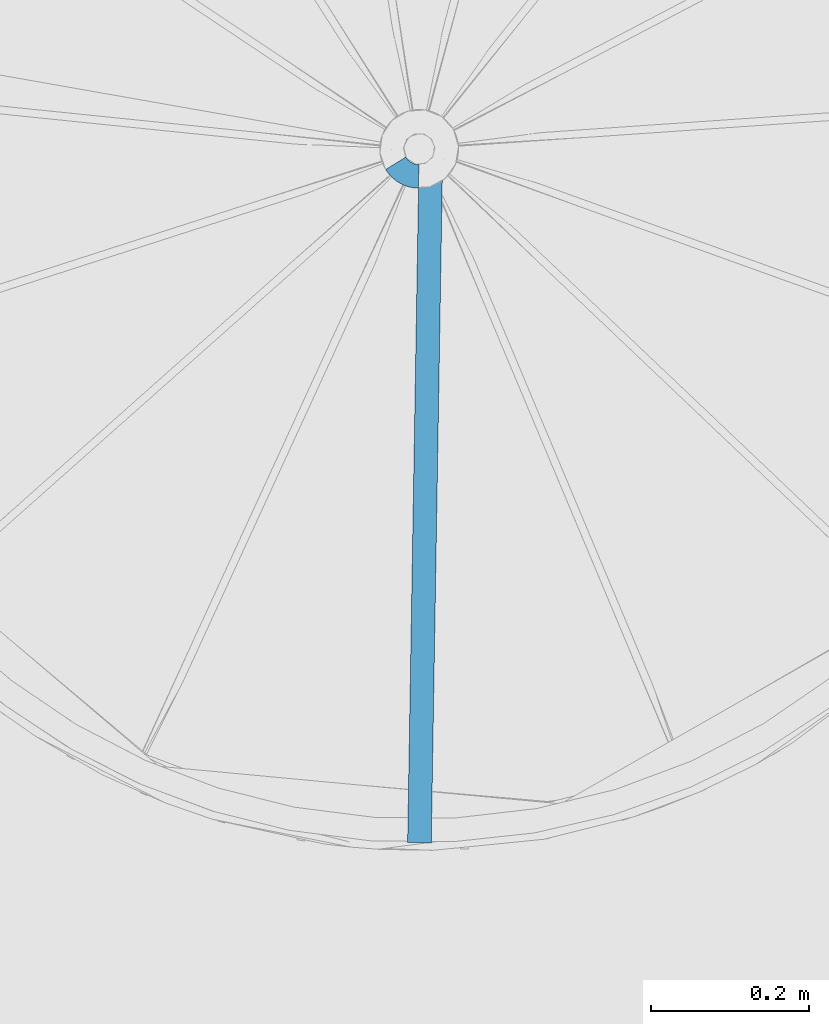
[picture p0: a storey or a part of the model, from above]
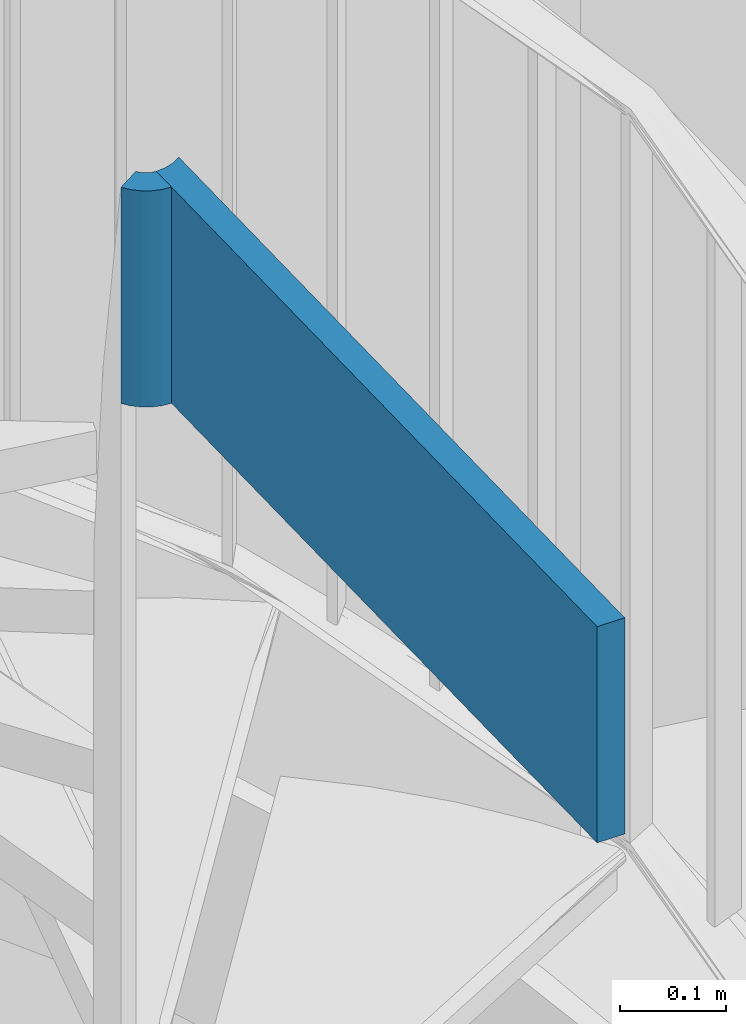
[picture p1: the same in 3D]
Properties of the parts of a building model (IFC2X3), part 1 of 2

# File
Description: ViewDefinition [CoordinationView_V2.0]
File name: 18021c
Time: 2021-05-19T17:37:48
Written by: The EXPRESS Data Manager Version 5.02.0100.07 : 28 Aug 2013
Made in: 20200826_1250(x64) - Exporter 20.2.1.0 - Alternate UI 20.2.1.0
Comment: STEP Physical File produced by: The EXPRESS Data Manager Version 5.02.0100.07 : 28 Aug 2013 * Module: EDMstepFileFactory/EDMstandAlone * Creation date: Wed May 19 17:37:48 2021 * Host: WS-1905 * Database: C:\Users\HDC~1.RDH\AppData\Local\Temp\51318361-dd76-45ec-ba82-957046c431c0\c4a6451b-f70e-414c-8df4-ee8861f415a2\ifc * Database version: 5507 * Database creation date: Wed May 19 17:37:37 2021 * Schema: IFC2X3 * Model: DataRepository.ifc * Model creation date: Wed May 19 17:37:37 2021 * Header model: DataRepository.ifc_HeaderModel * Header model creation date: Wed May 19 17:37:37 2021 * EDMuser: sdai-user * EDMgroup: sdai-group * License ID and type: 5605 : Permanent license. Expiry date: * EDMstepFileFactory options: 020000

# IfcProject, 18021c
LongName: JRCZ Fase 3 Ecologie; Phase: DO

# IfcSite, <Kadaster Gemeente>;<Kadaster nummer>;<Kadaster sectie>
RefLatitude: 51, 29, 42, 435607; RefLongitude: 3, 36, 32, 61710; RefElevation: 0 mm
Pset_ProductRequirements - Category: Project Information

# IfcBuilding, JRCZ Middelburg
LongName: JRCZ Middelburg
Pset_BuildingCommon - NumberOfStoreys: 5
Pset_ProductRequirements - Category: Project Information

# IfcBuildingStorey: Level:00_level_rechts_1.8mm verkort (5)
In: JRCZ Middelburg
Pset_ProductRequirements - Category: Levels
Name | LongName = Pset_AirSideSystemInformation, Name = Pset_ProductRequirements, Name | Elevation (mm)
-1 kelder | -1 kelder | -4000
00 begane grond | 00 begane grond | 0
01 eerste verdieping | 01 eerste verdieping | 3000
02 tweede verdieping | 02 tweede verdieping | 3700
03 dak | 03 dak | 6000

# IfcBeam: M_Dimension Lumber:180x550 (4)
Type - Pset_BeamCommon - IsExternal: no; LoadBearing: yes; Reference: 180x550
Type - Pset_ProductRequirements - Category: Structural Framing
Type - Pset_QuantityTakeOff - Reference: 180x550
Type - Pset_ReinforcementBarPitchOfBeam - Reference: 180x550
Material: Softwood, Lumber
Pset_BeamCommon - Slope: 0 deg
Pset_QuantityTakeOff - sets with these values: 2
Name (M_Dimension Lumber:180x550:...) | In | Span (mm)
1747457 | 01 eerste verdieping | 5968.59
1747506 | 01 eerste verdieping | 5680
1748045 | 02 tweede verdieping | 6266.1
1748047 | 02 tweede verdieping | 6533.1

# IfcBeam: M_Dimension Lumber:71 x 271 (31)
In: 01 eerste verdieping
Type - Pset_BeamCommon - IsExternal: no; LoadBearing: yes; Reference: 71 x 271
Type - Pset_ProductRequirements - Category: Structural Framing
Type - Pset_QuantityTakeOff - Reference: 71 x 271
Type - Pset_ReinforcementBarPitchOfBeam - Reference: 71 x 271
Material: Softwood, Lumber
Pset_BeamCommon - Slope: 0 deg; Span: 7200 mm
Pset_QuantityTakeOff - sets with these values: 2
Name (M_Dimension Lumber:71 x 271:...)
2881486
2881488
2881490
2881492
2881494
2881496
2881498
2881500
2881502
2881504
2881506
2881508
2881510
2881512
2881514
2881516
2881518
2881520
2881522
2881524
2881526
2881528
2881530
2881532
2881534
2881536
2881538
2881540
2881542
2881544
2881546

# IfcBuildingElementProxy: Hogeschool gebouw1:Hogeschool gebouw, Hogeschool gebouw1:Hogeschool gebouw:2096273
In: 00 begane grond
Type - Material: Default wit
Type - Pset_BuildingElementProxyCommon - Reference: Hogeschool gebouw
Type - Pset_ProductRequirements - Category: Mass
Type - Pset_QuantityTakeOff - Reference: Hogeschool gebouw
Material: Default wit (6)
Pset_BuildingElementProxyCommon - sets with these values: 2

# IfcBuildingElementProxy: Kolommen:Kolommen, Kolommen:Kolommen:2648048
In: 00 begane grond
Type - Material: Staal
Type - Pset_BuildingElementProxyCommon - Reference: Kolommen
Type - Pset_ProductRequirements - Category: Generic Models
Type - Pset_QuantityTakeOff - Reference: Kolommen
Material: Staal (17), Beton
Pset_BuildingElementProxyCommon - sets with these values: 2
Pset_ProvisionForVoid - Width: 4960 mm; Depth: 4960 mm

# IfcBuildingElementProxy: lbk 3:lbk 1, lbk 3:lbk 1:1831866
In: 03 dak
Type - Material: Default wit
Type - Pset_BuildingElementProxyCommon - Reference: lbk 1
Type - Pset_ProductRequirements - Category: Mass
Type - Pset_QuantityTakeOff - Reference: lbk 1
Pset_BuildingElementProxyCommon - sets with these values: 2
Pset_ProvisionForVoid - Width: 1100 mm; Height: 1300 mm; Depth: 1100 mm

# IfcBuildingElementProxy: lbk 4:lbk 1, lbk 4:lbk 1:1831894
In: 03 dak
Type - Material: Default wit
Type - Pset_BuildingElementProxyCommon - Reference: lbk 1
Type - Pset_ProductRequirements - Category: Mass
Type - Pset_QuantityTakeOff - Reference: lbk 1
Pset_BuildingElementProxyCommon - sets with these values: 2
Pset_ProvisionForVoid - Width: 1100 mm; Height: 1300 mm; Depth: 1100 mm

# IfcBuildingElementProxy: waterbak2:waterbak, waterbak2:waterbak:2452146
In: 02 tweede verdieping
Type - Material: Default wit
Type - Pset_BuildingElementProxyCommon - Reference: waterbak
Type - Pset_ProductRequirements - Category: Mass
Type - Pset_QuantityTakeOff - Reference: waterbak
Pset_BuildingElementProxyCommon - sets with these values: 2
Pset_ProvisionForVoid - Width: 900 mm; Depth: 900 mm

# IfcBuildingElementProxy: waterbak3:waterbak, waterbak3:waterbak:2452175
In: 02 tweede verdieping
Type - Material: Default wit
Type - Pset_BuildingElementProxyCommon - Reference: waterbak
Type - Pset_ProductRequirements - Category: Mass
Type - Pset_QuantityTakeOff - Reference: waterbak
Pset_BuildingElementProxyCommon - sets with these values: 2
Pset_ProvisionForVoid - Width: 900 mm; Depth: 900 mm

# IfcColumn: M_Timber-Column:180x180 (3)
In: 00 begane grond
Type - PredefinedType: COLUMN; Material: Softwood, Lumber
Type - Pset_ColumnCommon - IsExternal: no; Reference: 180x180; LoadBearing: yes
Type - Pset_ProductRequirements - Category: Structural Columns
Type - Pset_QuantityTakeOff - Reference: 180x180
Type - Pset_ReinforcementBarPitchOfColumn - Reference: 180x180
Pset_QuantityTakeOff - sets with these values: 2
Name (M_Timber-Column:180x180:...) | Slope (deg)
1657394 | 0
1657616 | 0
1657631

# IfcCurtainWall: Curtain Wall:NLRS_28_CW_hsb rek 63x196mm h.o.h. 1200mm 2 (7)
Type - Pset_CurtainWallCommon - IsExternal: no; Reference: NLRS_28_CW_hsb rek 63x196mm h.o.h. 1200mm 2
Type - Pset_ManufacturerTypeInformation - Manufacturer: ITANNEX
Type - Pset_ProductRequirements - Category: Walls
Type - Pset_QuantityTakeOff - Reference: NLRS_28_CW_hsb rek 63x196mm h.o.h. 1200mm 2
Pset_CurtainWallCommon - IsExternal: yes
Name (Curtain Wall:NLRS_28_CW_hsb rek 63x196mm h.o.h. 1200mm 2:...) | In
2779010 | 01 eerste verdieping
2779018 | 01 eerste verdieping
2779360 | 01 eerste verdieping
2779361 | 01 eerste verdieping
2780039 | 02 tweede verdieping
2780053 | 02 tweede verdieping
2780060 | 02 tweede verdieping

# IfcCurtainWall: Curtain Wall:NLRS_28_CW_hsb rek 63x196mm h.o.h. 800mm, Curtain Wall:NLRS_28_CW_hsb rek 63x196mm h.o.h. 800mm:2779345
In: 01 eerste verdieping
Type - Pset_CurtainWallCommon - IsExternal: no; Reference: NLRS_28_CW_hsb rek 63x196mm h.o.h. 800mm
Type - Pset_ManufacturerTypeInformation - Manufacturer: ITANNEX
Type - Pset_ProductRequirements - Category: Walls
Type - Pset_QuantityTakeOff - Reference: NLRS_28_CW_hsb rek 63x196mm h.o.h. 800mm
Pset_CurtainWallCommon - IsExternal: yes

# IfcCurtainWall: Curtain Wall:NLRS_31_CW_Ontwerpkozijn 067x114 (6)
Type - Pset_CurtainWallCommon - IsExternal: no; Reference: NLRS_31_CW_Ontwerpkozijn 067x114
Type - Pset_ManufacturerTypeInformation - Manufacturer: ITANNEX
Type - Pset_ProductRequirements - Category: Walls
Type - Pset_QuantityTakeOff - Reference: NLRS_31_CW_Ontwerpkozijn 067x114
Name (Curtain Wall:NLRS_31_CW_Ontwerpkozijn 067x114:...) | In | Group
1771511 | 00 begane grond | Model Group:H05:2174889 | Pset_CurtainWallCommon - IsExternal: yes
1830644 | 00 begane grond | Model Group:H04:1830654 | Pset_CurtainWallCommon - IsExternal: yes
2359723 | 02 tweede verdieping | Model Group:H01:2359729 | Pset_OpeningElementCommon - Reference: NLRS_31_CW_Ontwerpkozijn 067x114; sets with these values: 2
2384861 | 00 begane grond | Model Group:H02:1830591 | Pset_OpeningElementCommon - Reference: NLRS_31_CW_Ontwerpkozijn 067x114; sets with these values: 2
2384906 | 00 begane grond | Model Group:H03:2384882 | Pset_OpeningElementCommon - Reference: NLRS_31_CW_Ontwerpkozijn 067x114; sets with these values: 2
2775503 | 00 begane grond | Model Group:H02:1978079 | Pset_CurtainWallCommon - IsExternal: yes

# IfcCurtainWall: Curtain Wall:NLRS_31_CW_Ontwerpkozijn 067x114 2 (23)
Type - Pset_CurtainWallCommon - IsExternal: no; Reference: NLRS_31_CW_Ontwerpkozijn 067x114 2
Type - Pset_ManufacturerTypeInformation - Manufacturer: ITANNEX
Type - Pset_ProductRequirements - Category: Walls
Type - Pset_QuantityTakeOff - Reference: NLRS_31_CW_Ontwerpkozijn 067x114 2
Name (Curtain Wall:NLRS_31_CW_Ontwerpkozijn 067x114 2:...) | In | IsExternal | Group
2287266 | 01 eerste verdieping | yes | Model Group:H07:2287249
2760790 | 00 begane grond | yes | Model Group:H08:2161338
2760800 | 00 begane grond | yes | Model Group:H08:2161338
2760810 | 00 begane grond | yes | Model Group:H08:2161338
2760820 | 00 begane grond | yes | Model Group:H08:2161338
2760830 | 00 begane grond | yes | Model Group:H08:2161338
2760840 | 00 begane grond | yes | Model Group:H08:2161338
2760850 | 00 begane grond | yes | Model Group:H08:2161338
2760860 | 00 begane grond | yes | Model Group:H08:2161338
2760870 | 00 begane grond | yes | Model Group:H08:2161338
2760880 | 00 begane grond | yes | Model Group:H08:2161338
2760890 | 00 begane grond | yes | Model Group:H08:2161338
2761305 | 02 tweede verdieping |  | Model Group:H09:1979223 | Pset_OpeningElementCommon - Reference: NLRS_31_CW_Ontwerpkozijn 067x114 2; sets with these values: 2
2761315 | 02 tweede verdieping |  | Model Group:H09:1979223 | Pset_OpeningElementCommon - Reference: NLRS_31_CW_Ontwerpkozijn 067x114 2; sets with these values: 2
2763741 | 02 tweede verdieping | yes | Model Group:H10:2055879
2763751 | 02 tweede verdieping | yes | Model Group:H10:2055879
2763761 | 02 tweede verdieping | yes | Model Group:H10:2055879
2763771 | 02 tweede verdieping | yes | Model Group:H10:2055879
2763781 | 02 tweede verdieping | yes | Model Group:H10:2055879
2763791 | 02 tweede verdieping | yes | Model Group:H10:2055879
2764322 | 02 tweede verdieping |  | Model Group:H11:2764105 | Pset_OpeningElementCommon - Reference: NLRS_31_CW_Ontwerpkozijn 067x114 2; sets with these values: 2
2764332 | 02 tweede verdieping |  | Model Group:H11:2764105 | Pset_OpeningElementCommon - Reference: NLRS_31_CW_Ontwerpkozijn 067x114 2; sets with these values: 2
2764342 | 02 tweede verdieping |  | Model Group:H11:2764105 | Pset_OpeningElementCommon - Reference: NLRS_31_CW_Ontwerpkozijn 067x114 2; sets with these values: 2

# IfcCurtainWall: Curtain Wall:NLRS_31_CW_hsb rek 63x196mm h.o.h. 800mm (23)
Type - Pset_CurtainWallCommon - IsExternal: no; Reference: NLRS_31_CW_hsb rek 63x196mm h.o.h. 800mm
Type - Pset_ManufacturerTypeInformation - Manufacturer: ITANNEX
Type - Pset_ProductRequirements - Category: Walls
Type - Pset_QuantityTakeOff - Reference: NLRS_31_CW_hsb rek 63x196mm h.o.h. 800mm
Name (Curtain Wall:NLRS_31_CW_hsb rek 63x196mm h.o.h. 800mm:...) | In | IsExternal | Group
2287262 | 01 eerste verdieping | yes | Model Group:H07:2287249
2760786 | 00 begane grond | yes | Model Group:H08:2161338
2760796 | 00 begane grond | yes | Model Group:H08:2161338
2760806 | 00 begane grond | yes | Model Group:H08:2161338
2760816 | 00 begane grond | yes | Model Group:H08:2161338
2760826 | 00 begane grond | yes | Model Group:H08:2161338
2760836 | 00 begane grond | yes | Model Group:H08:2161338
2760846 | 00 begane grond | yes | Model Group:H08:2161338
2760856 | 00 begane grond | yes | Model Group:H08:2161338
2760866 | 00 begane grond | yes | Model Group:H08:2161338
2760876 | 00 begane grond | yes | Model Group:H08:2161338
2760886 | 00 begane grond | yes | Model Group:H08:2161338
2761301 | 02 tweede verdieping |  | Model Group:H09:1979223 | Pset_OpeningElementCommon - Reference: NLRS_31_CW_hsb rek 63x196mm h.o.h. 800mm; sets with these values: 2
2761311 | 02 tweede verdieping |  | Model Group:H09:1979223 | Pset_OpeningElementCommon - Reference: NLRS_31_CW_hsb rek 63x196mm h.o.h. 800mm; sets with these values: 2
2763737 | 02 tweede verdieping | yes | Model Group:H10:2055879
2763747 | 02 tweede verdieping | yes | Model Group:H10:2055879
2763757 | 02 tweede verdieping | yes | Model Group:H10:2055879
2763767 | 02 tweede verdieping | yes | Model Group:H10:2055879
2763777 | 02 tweede verdieping | yes | Model Group:H10:2055879
2763787 | 02 tweede verdieping | yes | Model Group:H10:2055879
2764318 | 02 tweede verdieping |  | Model Group:H11:2764105 | Pset_OpeningElementCommon - Reference: NLRS_31_CW_hsb rek 63x196mm h.o.h. 800mm; sets with these values: 2
2764328 | 02 tweede verdieping |  | Model Group:H11:2764105 | Pset_OpeningElementCommon - Reference: NLRS_31_CW_hsb rek 63x196mm h.o.h. 800mm; sets with these values: 2
2764338 | 02 tweede verdieping |  | Model Group:H11:2764105 | Pset_OpeningElementCommon - Reference: NLRS_31_CW_hsb rek 63x196mm h.o.h. 800mm; sets with these values: 2

# IfcCurtainWall: Curtain Wall:NLRS_32_CW_Ontwerpkozijn 067x114, Curtain Wall:NLRS_32_CW_Ontwerpkozijn 067x114:2362233
In: 00 begane grond
Type - Pset_CurtainWallCommon - IsExternal: no; Reference: NLRS_32_CW_Ontwerpkozijn 067x114
Type - Pset_ManufacturerTypeInformation - Manufacturer: ITANNEX
Type - Pset_ProductRequirements - Category: Walls
Type - Pset_QuantityTakeOff - Reference: NLRS_32_CW_Ontwerpkozijn 067x114
Pset_OpeningElementCommon - Reference: NLRS_32_CW_Ontwerpkozijn 067x114; sets with these values: 2
Group: Model Group:H06:2017390

# IfcCurtainWall: Curtain Wall:NLRS_32_CW_Ontwerpkozijn 067x114 binnen (4)
Type - Pset_CurtainWallCommon - IsExternal: no; Reference: NLRS_32_CW_Ontwerpkozijn 067x114 binnen
Type - Pset_ManufacturerTypeInformation - Manufacturer: ITANNEX
Type - Pset_ProductRequirements - Category: Walls
Type - Pset_QuantityTakeOff - Reference: NLRS_32_CW_Ontwerpkozijn 067x114 binnen
Name (Curtain Wall:NLRS_32_CW_Ontwerpkozijn 067x114 binnen:...) | In | Reference | sets with these values
1745974 | 00 begane grond | NLRS_32_CW_Ontwerpkozijn 067x114 binnen | 2
1766168 | 00 begane grond | NLRS_32_CW_Ontwerpkozijn 067x114 binnen | 2
1772871 | 02 tweede verdieping | NLRS_32_CW_Ontwerpkozijn 067x114 binnen | 2 | Group: Model Group:32_dubbele deur:2147310
1820701 | 00 begane grond | Group: Model Group:32_kozijn_meterkast:1986720; Pset_CurtainWallCommon - IsExternal: yes

# IfcCurtainWall: Curtain Wall:Vliesgevel C, Curtain Wall:Vliesgevel C:2317173
In: 00 begane grond
Type - Pset_CurtainWallCommon - IsExternal: no; Reference: Vliesgevel C
Type - Pset_ManufacturerTypeInformation - Manufacturer: ITANNEX
Type - Pset_ProductRequirements - Category: Walls
Type - Pset_QuantityTakeOff - Reference: Vliesgevel C
Pset_CurtainWallCommon - IsExternal: yes
Group: Model Group:vliesgevel C:2317233

# IfcCurtainWall: Curtain Wall:vliesgevel A, Curtain Wall:vliesgevel A:1692366
In: 00 begane grond
Type - Pset_CurtainWallCommon - IsExternal: no; Reference: vliesgevel A
Type - Pset_ManufacturerTypeInformation - Manufacturer: ITANNEX
Type - Pset_ProductRequirements - Category: Walls
Type - Pset_QuantityTakeOff - Reference: vliesgevel A
Pset_CurtainWallCommon - IsExternal: yes
Group: Model Group:vliesgevel A:2175042

# IfcCurtainWall: Curtain Wall:vliesgevel B, Curtain Wall:vliesgevel B:1745524
In: 00 begane grond
Type - Pset_CurtainWallCommon - IsExternal: no; Reference: vliesgevel B
Type - Pset_ManufacturerTypeInformation - Manufacturer: ITANNEX
Type - Pset_ProductRequirements - Category: Walls
Type - Pset_QuantityTakeOff - Reference: vliesgevel B
Pset_CurtainWallCommon - IsExternal: yes
Group: Model Group:Vliesgevel B:2773624

# IfcDistributionPort (6)
Description: Flow
Name | FlowDirection
2 x Port_1755777 | SOURCE
Port_1755777 | SINK
2 x Port_1786391 | SOURCE
Port_1786391 | SINK

# IfcDoor: 31_DO_deur_0:binnendeur (2)
In: 00 begane grond
Type - ParameterTakesPrecedence: no; Sizeable: no; Material: <Unnamed> (2)
Type - Pset_DoorCommon - IsExternal: no; Reference: binnendeur
Type - Pset_ManufacturerTypeInformation - Manufacturer: ITANNEX
Type - Pset_ProductRequirements - Category: Doors
Type - Pset_QuantityTakeOff - Reference: binnendeur
OverallHeight: 1933 mm; Group: Model Group:32_kozijn_meterkast:1986720
Pset_DoorCommon - IsExternal: yes
Name (31_DO_deur_0:binnendeur:...) | OverallWidth (mm)
1820702 | 557.55
1820844 | 588.45

# IfcDoor: 31_DO_deur_0:binnendeur 2 (2)
In: 00 begane grond
Type - ParameterTakesPrecedence: no; Sizeable: no; Material: <Unnamed> (2)
Type - Pset_DoorCommon - IsExternal: no; Reference: binnendeur 2
Type - Pset_ManufacturerTypeInformation - Manufacturer: ITANNEX
Type - Pset_ProductRequirements - Category: Doors
Type - Pset_QuantityTakeOff - Reference: binnendeur 2
OverallHeight: 2333 mm; Group: Model Group:H06:2017390
Pset_DoorCommon - IsExternal: yes
Name (31_DO_deur_0:binnendeur 2:...) | OverallWidth (mm)
2362234 | 557.55
2362239 | 588.45

# IfcDoor: 31_DO_deur_0:deur (6)
Type - ParameterTakesPrecedence: no; Sizeable: no; Material: RBM_a_deur_paneel (2)
Type - Pset_DoorCommon - IsExternal: no; Reference: deur
Type - Pset_ManufacturerTypeInformation - Manufacturer: ITANNEX
Type - Pset_ProductRequirements - Category: Doors
Type - Pset_QuantityTakeOff - Reference: deur
OverallHeight: 2333 mm
Pset_DoorCommon - IsExternal: yes
Name (31_DO_deur_0:deur:...) | In | OverallWidth (mm) | Group
1830645 | 00 begane grond | 833 | Model Group:H04:1830654
1830651 | 00 begane grond | 833 | Model Group:H04:1830654
2359724 | 02 tweede verdieping | 930 | Model Group:H01:2359729
2384862 | 00 begane grond | 950 | Model Group:H02:1830591
2384907 | 00 begane grond | 950 | Model Group:H03:2384882
2775504 | 00 begane grond | 950 | Model Group:H02:1978079

# IfcDoor: 31_DO_schuifdeur_1:binnendeur, 31_DO_schuifdeur_1:binnendeur:2536623
In: 00 begane grond
Type - ParameterTakesPrecedence: no; Sizeable: no; Material: RBM_i2_binnenkozijn (2)
Type - Pset_DoorCommon - IsExternal: no; Reference: binnendeur
Type - Pset_ManufacturerTypeInformation - Manufacturer: ITANNEX
Type - Pset_ProductRequirements - Category: Doors
Type - Pset_QuantityTakeOff - Reference: binnendeur
OverallHeight: 2211.17 mm; OverallWidth: 2298.02 mm; Material: RBM_i2_binnenkozijn (4); Group: Model Group:Vliesgevel B:2773624
Pset_DoorCommon - IsExternal: yes

# IfcDoor: 31_DO_schuifdeur_1:deur, 31_DO_schuifdeur_1:deur:1693376
In: 00 begane grond
Type - ParameterTakesPrecedence: no; Sizeable: no; Material: RBM_a_kozijn licht (2)
Type - Pset_DoorCommon - IsExternal: no; Reference: deur
Type - Pset_ManufacturerTypeInformation - Manufacturer: ITANNEX
Type - Pset_ProductRequirements - Category: Doors
Type - Pset_QuantityTakeOff - Reference: deur
OverallHeight: 2366.5 mm; OverallWidth: 2124.7 mm; Material: RBM_a_kozijn licht (4); Group: Model Group:vliesgevel A:2175042
Pset_DoorCommon - IsExternal: yes

# IfcDoor: 31_DO_stolpdeur_1:0std, 31_DO_stolpdeur_1:0std:1771512
In: 00 begane grond
Type - ParameterTakesPrecedence: no; Sizeable: no; Material: RBM_a_kozijn (2)
Type - Pset_DoorCommon - IsExternal: no; Reference: 0std
Type - Pset_ManufacturerTypeInformation - Manufacturer: ITANNEX
Type - Pset_ProductRequirements - Category: Doors
Type - Pset_QuantityTakeOff - Reference: 0std
OverallHeight: 2333 mm; OverallWidth: 1533 mm; Material: RBM_a_kozijn (4); Group: Model Group:H05:2174889
Pset_DoorCommon - IsExternal: yes

# IfcDoor: 31_DO_stolpdeur_1:0std, 31_DO_stolpdeur_1:0std:2317180
In: 00 begane grond
Type - ParameterTakesPrecedence: no; Sizeable: no; Material: RBM_a_kozijn licht (2)
Type - Pset_DoorCommon - IsExternal: no; Reference: 0std
Type - Pset_ManufacturerTypeInformation - Manufacturer: ITANNEX
Type - Pset_ProductRequirements - Category: Doors
Type - Pset_QuantityTakeOff - Reference: 0std
OverallHeight: 2366.5 mm; OverallWidth: 2122.45 mm; Material: RBM_a_kozijn licht (4); Group: Model Group:vliesgevel C:2317233
Pset_DoorCommon - IsExternal: yes

# IfcDoor: 31_DO_stolpdeur_1:0std binnendeur (2)
Type - ParameterTakesPrecedence: no; Sizeable: no; Material: <Unnamed> (2)
Type - Pset_DoorCommon - IsExternal: no; Reference: 0std binnendeur
Type - Pset_ManufacturerTypeInformation - Manufacturer: ITANNEX
Type - Pset_ProductRequirements - Category: Doors
Type - Pset_QuantityTakeOff - Reference: 0std binnendeur
OverallHeight: 2333 mm; Material: <Unnamed> (4)
Pset_DoorCommon - IsExternal: yes
Name (31_DO_stolpdeur_1:0std binnendeur:...) | In | OverallWidth (mm)
1766169 | 00 begane grond | 1533
1772872 | 02 tweede verdieping | 1433 | Group: Model Group:32_dubbele deur:2147310

# IfcDoor: NLRS_32_DO_ISR_onderdeel deur-SH_generiek_ISR:dichte deur_gen, NLRS_32_DO_ISR_onderdeel deur-SH_generiek_ISR:dichte deur_gen:1765288
In: 01 eerste verdieping
Type - OperationType: SINGLE_SWING_RIGHT; ConstructionType: USERDEFINED; ParameterTakesPrecedence: no; Sizeable: no; Material: <Unnamed> (2)
Type - NLRS_32_DO_ISR_onderdeel deur-SH_generiek_ISR:dichte deur_gen:1765288 - PanelOperation: SWINGING
Type - Pset_ConcreteElementGeneral - ConstructionType: deurblad
Type - Pset_DoorCommon - IsExternal: no; Reference: dichte deur_gen
Type - Pset_ProductRequirements - Category: Doors
Type - Pset_QuantityTakeOff - Reference: dichte deur_gen
OverallHeight: 2315 mm; OverallWidth: 930 mm; Material: <Unnamed>

# IfcDoor: NLRS_32_DO_ISR_onderdeel deur-SH_generiek_ISR:dichte deur_gen, NLRS_32_DO_ISR_onderdeel deur-SH_generiek_ISR:dichte deur_gen:1774227
In: 01 eerste verdieping
Type - OperationType: SINGLE_SWING_RIGHT; ConstructionType: USERDEFINED; ParameterTakesPrecedence: no; Sizeable: no; Material: <Unnamed> (2)
Type - NLRS_32_DO_ISR_onderdeel deur-SH_generiek_ISR:dichte deur_gen:1774227 - PanelOperation: SWINGING
Type - Pset_ConcreteElementGeneral - ConstructionType: deurblad
Type - Pset_DoorCommon - IsExternal: no; Reference: dichte deur_gen
Type - Pset_ProductRequirements - Category: Doors
Type - Pset_QuantityTakeOff - Reference: dichte deur_gen
OverallHeight: 2315 mm; OverallWidth: 980 mm; Material: <Unnamed>

# IfcDoor: NLRS_32_DO_ISR_onderdeel deur-SH_generiek_ISR:dichte deur_gen (7)
Type - OperationType: SINGLE_SWING_RIGHT; ConstructionType: USERDEFINED; ParameterTakesPrecedence: no; Sizeable: no; Material: <Unnamed> (2)
Type - NLRS_32_DO_ISR_onderdeel deur-SH_generiek_ISR:dichte deur_gen:1774258 - PanelOperation: SWINGING
Type - Pset_ConcreteElementGeneral - ConstructionType: deurblad
Type - Pset_DoorCommon - IsExternal: no; Reference: dichte deur_gen
Type - Pset_ProductRequirements - Category: Doors
Type - Pset_QuantityTakeOff - Reference: dichte deur_gen
OverallHeight: 2315 mm; OverallWidth: 980 mm; Material: <Unnamed>
Name (NLRS_32_DO_ISR_onderdeel deur-SH_generiek_ISR:dichte deur_gen:...) | In
1774258 | 01 eerste verdieping
1774293 | 01 eerste verdieping
1774882 | 00 begane grond
1775023 | 00 begane grond
1823580 | 01 eerste verdieping
1823676 | 01 eerste verdieping
1830939 | 00 begane grond

# IfcDoor: NLRS_32_DO_ISR_onderdeel deur-SH_generiek_ISR:dichte deur_gen, NLRS_32_DO_ISR_onderdeel deur-SH_generiek_ISR:dichte deur_gen:1986993
In: 01 eerste verdieping
Type - OperationType: SINGLE_SWING_RIGHT; ConstructionType: USERDEFINED; ParameterTakesPrecedence: no; Sizeable: no; Material: <Unnamed> (2)
Type - NLRS_32_DO_ISR_onderdeel deur-SH_generiek_ISR:dichte deur_gen:1986993 - PanelOperation: SWINGING
Type - Pset_ConcreteElementGeneral - ConstructionType: deurblad
Type - Pset_DoorCommon - IsExternal: no; Reference: dichte deur_gen
Type - Pset_ProductRequirements - Category: Doors
Type - Pset_QuantityTakeOff - Reference: dichte deur_gen
OverallHeight: 2315 mm; OverallWidth: 880 mm; Material: <Unnamed>

# IfcDoor: NLRS_32_DO_ISR_onderdeel deur-SH_generiek_ISR:dichte deur_gen, NLRS_32_DO_ISR_onderdeel deur-SH_generiek_ISR:dichte deur_gen:2352775
In: 01 eerste verdieping
Type - OperationType: SINGLE_SWING_RIGHT; ConstructionType: USERDEFINED; ParameterTakesPrecedence: no; Sizeable: no; Material: <Unnamed> (2)
Type - NLRS_32_DO_ISR_onderdeel deur-SH_generiek_ISR:dichte deur_gen:2352775 - PanelOperation: SWINGING
Type - Pset_ConcreteElementGeneral - ConstructionType: deurblad
Type - Pset_DoorCommon - IsExternal: no; Reference: dichte deur_gen
Type - Pset_ProductRequirements - Category: Doors
Type - Pset_QuantityTakeOff - Reference: dichte deur_gen
OverallHeight: 2315 mm; OverallWidth: 880 mm; Material: <Unnamed>

# IfcDoor: NLRS_32_DO_ISR_onderdeel deur-SH_generiek_ISR:dichte deur_gen, NLRS_32_DO_ISR_onderdeel deur-SH_generiek_ISR:dichte deur_gen:2530179
In: 00 begane grond
Type - OperationType: SINGLE_SWING_RIGHT; ConstructionType: USERDEFINED; ParameterTakesPrecedence: no; Sizeable: no; Material: <Unnamed> (2)
Type - NLRS_32_DO_ISR_onderdeel deur-SH_generiek_ISR:dichte deur_gen:2530179 - PanelOperation: SWINGING
Type - Pset_ConcreteElementGeneral - ConstructionType: deurblad
Type - Pset_DoorCommon - IsExternal: no; Reference: dichte deur_gen
Type - Pset_ProductRequirements - Category: Doors
Type - Pset_QuantityTakeOff - Reference: dichte deur_gen
OverallHeight: 2315 mm; OverallWidth: 600 mm; Material: <Unnamed>

# IfcDoor: NLRS_32_DO_UN_samenstelling binnenkozijn hout-SH_generiek_ISR:enkele deur_gen (12)
Type - ConstructionType: USERDEFINED; ParameterTakesPrecedence: no; Sizeable: no; Material: <Unnamed> (2)
Type - Pset_ConcreteElementGeneral - ConstructionType: binnenkozijn hout
Type - Pset_DoorCommon - IsExternal: no; Reference: enkele deur_gen
Type - Pset_ProductRequirements - Category: Doors
Type - Pset_QuantityTakeOff - Reference: enkele deur_gen
OverallHeight: 2377 mm; Material: <Unnamed> (3)
Name (NLRS_32_DO_UN_samenstelling binnenkozijn hout-SH_generiek_ISR:enkele deur_gen:...) | In | OverallWidth (mm)
1765287 | 01 eerste verdieping | 1034
1774226 | 01 eerste verdieping | 1084
1774257 | 01 eerste verdieping | 1084
1774292 | 01 eerste verdieping | 1084
1774881 | 00 begane grond | 1084
1775022 | 00 begane grond | 1084
1823579 | 01 eerste verdieping | 1084
1823675 | 01 eerste verdieping | 1084
1830938 | 00 begane grond | 1084
1986992 | 01 eerste verdieping | 984
2352774 | 01 eerste verdieping | 984
2530178 | 00 begane grond | 704

# IfcElementAssembly: Structural Beam System:houten balkalaag 71 X 271 hoh400, Structural Beam System:houten balkalaag 71 X 271 hoh400:2881297
In: 01 eerste verdieping
PredefinedType: BEAM_GRID
Pset_ProductRequirements - Category: Structural Beam Systems
Pset_QuantityTakeOff - Reference: houten balkalaag 71 X 271 hoh400

# IfcFlowTerminal: NLRS_74_PF_FB_toilet wand_generiek_ISR:toilet_gen (2)
Type - Classification: 74.11.11 (NL/SfB); Material: <Unnamed> (2)
Type - Pset_ProductRequirements - Category: Plumbing Fixtures
Type - Pset_QuantityTakeOff - Reference: toilet_gen
Material: <Unnamed> (3)
Pset_DistributionFlowElementCommon - Reference: toilet_gen; sets with these values: 2
Name (NLRS_74_PF_FB_toilet wand_generiek_ISR:toilet_gen:...) | In
1786344 | 00 begane grond
2353124 | 01 eerste verdieping

# IfcFlowTerminal: NLRS_74_PF_FB_wastafel_generiek_ISR:wastafel_gen (2)
Type - Classification: 74.11.31 (NL/SfB); Material: <Unnamed> (2)
Type - Pset_ProductRequirements - Category: Plumbing Fixtures
Type - Pset_QuantityTakeOff - Reference: wastafel_gen
Material: <Unnamed> (8)
Pset_DistributionFlowElementCommon - Reference: wastafel_gen; sets with these values: 2
Name (NLRS_74_PF_FB_wastafel_generiek_ISR:wastafel_gen:...) | In
1755777 | 01 eerste verdieping
1786391 | 00 begane grond

# IfcFurnishingElement: NLRS_73_FUS_UN_blad_generiek_generiek_ISR:blad_gen, NLRS_73_FUS_UN_blad_generiek_generiek_ISR:blad_gen:1775840
In: 00 begane grond
Type - Classification: 73.11 vaste keukenvoorzieningen; standaard, keukenmeubilering (NL/SfB); Material: <Unnamed>
Type - Pset_ProductRequirements - Category: Furniture Systems
Type - Pset_QuantityTakeOff - Reference: blad_gen
Pset_FurnitureTypeCommon - Description: aanrechtblad

# IfcMember: Rectangular Mullion:31_CWM_067x114 (111)
Type - PredefinedType: MULLION; Classification: 31.0 (NL/SfB); Material: RBM_a_kozijn
Type - Pset_ManufacturerTypeInformation - Manufacturer: ITANNEX
Type - Pset_MemberCommon - IsExternal: no; Reference: 31_CWM_067x114
Type - Pset_ProductRequirements - Category: Curtain Wall Mullions
Type - Pset_QuantityTakeOff - Reference: 31_CWM_067x114
Pset_MemberCommon - IsExternal: yes
Name (Rectangular Mullion:31_CWM_067x114:...) | In | Span (mm) | Group
1771514 | 00 begane grond | 1533 | Model Group:H05:2174889
1771516 | 00 begane grond | 2400 | Model Group:H05:2174889
1771517 | 00 begane grond | 2400 | Model Group:H05:2174889
1830646 | 00 begane grond | 900 | Model Group:H04:1830654
1830647 | 00 begane grond | 2333 | Model Group:H04:1830654
1830648 | 00 begane grond | 2333 | Model Group:H04:1830654
1830653 | 00 begane grond | 900 | Model Group:H04:1830654
2287268 | 01 eerste verdieping | 641 | Model Group:H07:2287249
2287269 | 01 eerste verdieping | 641 | Model Group:H07:2287249
2287270 | 01 eerste verdieping | 1400 | Model Group:H07:2287249
2287271 | 01 eerste verdieping | 1400 | Model Group:H07:2287249
2359725 | 02 tweede verdieping | 930 | Model Group:H01:2359729
2359726 | 02 tweede verdieping | 2400 | Model Group:H01:2359729
2359727 | 02 tweede verdieping | 2400 | Model Group:H01:2359729
2384863 | 00 begane grond | 950 | Model Group:H02:1830591
2384864 | 00 begane grond | 2400 | Model Group:H02:1830591
2384865 | 00 begane grond | 2400 | Model Group:H02:1830591
2384908 | 00 begane grond | 950 | Model Group:H03:2384882
2384909 | 00 begane grond | 2400 | Model Group:H03:2384882
2384910 | 00 begane grond | 2400 | Model Group:H03:2384882
2760792 | 00 begane grond | 641 | Model Group:H08:2161338
2760793 | 00 begane grond | 641 | Model Group:H08:2161338
2760794 | 00 begane grond | 1200 | Model Group:H08:2161338
2760795 | 00 begane grond | 1200 | Model Group:H08:2161338
2760802 | 00 begane grond | 641 | Model Group:H08:2161338
2760803 | 00 begane grond | 641 | Model Group:H08:2161338
2760804 | 00 begane grond | 1600 | Model Group:H08:2161338
2760805 | 00 begane grond | 1600 | Model Group:H08:2161338
2760812 | 00 begane grond | 641 | Model Group:H08:2161338
2760813 | 00 begane grond | 641 | Model Group:H08:2161338
2760814 | 00 begane grond | 1400 | Model Group:H08:2161338
2760815 | 00 begane grond | 1400 | Model Group:H08:2161338
2760822 | 00 begane grond | 641 | Model Group:H08:2161338
2760823 | 00 begane grond | 641 | Model Group:H08:2161338
2760824 | 00 begane grond | 1400 | Model Group:H08:2161338
2760825 | 00 begane grond | 1400 | Model Group:H08:2161338
2760832 | 00 begane grond | 641 | Model Group:H08:2161338
2760833 | 00 begane grond | 641 | Model Group:H08:2161338
2760834 | 00 begane grond | 1200 | Model Group:H08:2161338
2760835 | 00 begane grond | 1200 | Model Group:H08:2161338
2760842 | 00 begane grond | 641 | Model Group:H08:2161338
2760843 | 00 begane grond | 641 | Model Group:H08:2161338
2760844 | 00 begane grond | 1400 | Model Group:H08:2161338
2760845 | 00 begane grond | 1400 | Model Group:H08:2161338
2760852 | 00 begane grond | 641 | Model Group:H08:2161338
2760853 | 00 begane grond | 641 | Model Group:H08:2161338
2760854 | 00 begane grond | 1600 | Model Group:H08:2161338
2760855 | 00 begane grond | 1600 | Model Group:H08:2161338
2760862 | 00 begane grond | 641 | Model Group:H08:2161338
2760863 | 00 begane grond | 641 | Model Group:H08:2161338
2760864 | 00 begane grond | 1800 | Model Group:H08:2161338
2760865 | 00 begane grond | 1800 | Model Group:H08:2161338
2760872 | 00 begane grond | 641 | Model Group:H08:2161338
2760873 | 00 begane grond | 641 | Model Group:H08:2161338
2760874 | 00 begane grond | 1600 | Model Group:H08:2161338
2760875 | 00 begane grond | 1600 | Model Group:H08:2161338
2760882 | 00 begane grond | 641 | Model Group:H08:2161338
2760883 | 00 begane grond | 641 | Model Group:H08:2161338
2760884 | 00 begane grond | 1400 | Model Group:H08:2161338
2760885 | 00 begane grond | 1400 | Model Group:H08:2161338
2760892 | 00 begane grond | 641 | Model Group:H08:2161338
2760893 | 00 begane grond | 641 | Model Group:H08:2161338
2760894 | 00 begane grond | 1600 | Model Group:H08:2161338
2760895 | 00 begane grond | 1600 | Model Group:H08:2161338
2761307 | 02 tweede verdieping | 641 | Model Group:H09:1979223
2761308 | 02 tweede verdieping | 641 | Model Group:H09:1979223
2761309 | 02 tweede verdieping | 1200 | Model Group:H09:1979223
2761310 | 02 tweede verdieping | 1200 | Model Group:H09:1979223
2761317 | 02 tweede verdieping | 641 | Model Group:H09:1979223
2761318 | 02 tweede verdieping | 641 | Model Group:H09:1979223
2761319 | 02 tweede verdieping | 1200 | Model Group:H09:1979223
2761320 | 02 tweede verdieping | 1200 | Model Group:H09:1979223
2763743 | 02 tweede verdieping | 641 | Model Group:H10:2055879
2763744 | 02 tweede verdieping | 641 | Model Group:H10:2055879
2763745 | 02 tweede verdieping | 1600 | Model Group:H10:2055879
2763746 | 02 tweede verdieping | 1600 | Model Group:H10:2055879
2763753 | 02 tweede verdieping | 641 | Model Group:H10:2055879
2763754 | 02 tweede verdieping | 641 | Model Group:H10:2055879
2763755 | 02 tweede verdieping | 1400 | Model Group:H10:2055879
2763756 | 02 tweede verdieping | 1400 | Model Group:H10:2055879
2763763 | 02 tweede verdieping | 641 | Model Group:H10:2055879
2763764 | 02 tweede verdieping | 641 | Model Group:H10:2055879
2763765 | 02 tweede verdieping | 1400 | Model Group:H10:2055879
2763766 | 02 tweede verdieping | 1400 | Model Group:H10:2055879
2763773 | 02 tweede verdieping | 641 | Model Group:H10:2055879
2763774 | 02 tweede verdieping | 641 | Model Group:H10:2055879
2763775 | 02 tweede verdieping | 1600 | Model Group:H10:2055879
2763776 | 02 tweede verdieping | 1600 | Model Group:H10:2055879
2763783 | 02 tweede verdieping | 641 | Model Group:H10:2055879
2763784 | 02 tweede verdieping | 641 | Model Group:H10:2055879
2763785 | 02 tweede verdieping | 1600 | Model Group:H10:2055879
2763786 | 02 tweede verdieping | 1600 | Model Group:H10:2055879
2763793 | 02 tweede verdieping | 641 | Model Group:H10:2055879
2763794 | 02 tweede verdieping | 641 | Model Group:H10:2055879
2763795 | 02 tweede verdieping | 1600 | Model Group:H10:2055879
2763796 | 02 tweede verdieping | 1600 | Model Group:H10:2055879
2764324 | 02 tweede verdieping | 641 | Model Group:H11:2764105
2764325 | 02 tweede verdieping | 641 | Model Group:H11:2764105
2764326 | 02 tweede verdieping | 1600 | Model Group:H11:2764105
2764327 | 02 tweede verdieping | 1600 | Model Group:H11:2764105
2764334 | 02 tweede verdieping | 641 | Model Group:H11:2764105
2764335 | 02 tweede verdieping | 641 | Model Group:H11:2764105
2764336 | 02 tweede verdieping | 1600 | Model Group:H11:2764105
2764337 | 02 tweede verdieping | 1600 | Model Group:H11:2764105
2764344 | 02 tweede verdieping | 641 | Model Group:H11:2764105
2764345 | 02 tweede verdieping | 641 | Model Group:H11:2764105
2764346 | 02 tweede verdieping | 1600 | Model Group:H11:2764105
2764347 | 02 tweede verdieping | 1600 | Model Group:H11:2764105
2775505 | 00 begane grond | 950 | Model Group:H02:1978079
2775506 | 00 begane grond | 2400 | Model Group:H02:1978079
2775507 | 00 begane grond | 2400 | Model Group:H02:1978079

# IfcMember: Rectangular Mullion:31_CWM_067x114 vliesgevel (70)
In: 00 begane grond
Type - PredefinedType: MULLION; Material: RBM_a_kozijn licht
Type - Pset_MemberCommon - IsExternal: no; Reference: 31_CWM_067x114 vliesgevel
Type - Pset_ProductRequirements - Category: Curtain Wall Mullions
Type - Pset_QuantityTakeOff - Reference: 31_CWM_067x114 vliesgevel
Pset_MemberCommon - IsExternal: yes
Name (Rectangular Mullion:31_CWM_067x114 vliesgevel:...) | Span (mm) | Group
1692369 | 1088.69 | Model Group:vliesgevel A:2175042
1692370 | 1018.56 | Model Group:vliesgevel A:2175042
1692371 | 2400 | Model Group:vliesgevel A:2175042
1692372 | 2630.8 | Model Group:vliesgevel A:2175042
1693382 | 1142.76 | Model Group:vliesgevel A:2175042
1693384 | 2299.5 | Model Group:vliesgevel A:2175042
1693456 | 1142.76 | Model Group:vliesgevel A:2175042
1693524 | 1088.61 | Model Group:vliesgevel A:2175042
1693525 | 1173.06 | Model Group:vliesgevel A:2175042
1693526 | 2299.5 | Model Group:vliesgevel A:2175042
1693767 | 1200 | Model Group:vliesgevel A:2175042
1693768 | 2400 | Model Group:vliesgevel A:2175042
1693769 | 1018.56 | Model Group:vliesgevel A:2175042
1693770 | 1139.56 | Model Group:vliesgevel A:2175042
1693771 | 1139.56 | Model Group:vliesgevel A:2175042
1693772 | 1018.64 | Model Group:vliesgevel A:2175042
1693773 | 1133 | Model Group:vliesgevel A:2175042
1693774 | 1133 | Model Group:vliesgevel A:2175042
1693775 | 1133 | Model Group:vliesgevel A:2175042
1693857 | 2964.57 | Model Group:vliesgevel A:2175042
1693858 | 1200 | Model Group:vliesgevel A:2175042
1693859 | 1018.56 | Model Group:vliesgevel A:2175042
1693860 | 1139.56 | Model Group:vliesgevel A:2175042
1693861 | 1139.56 | Model Group:vliesgevel A:2175042
1693862 | 1018.64 | Model Group:vliesgevel A:2175042
1693863 | 2678.72 | Model Group:vliesgevel A:2175042
1693864 | 2764.19 | Model Group:vliesgevel A:2175042
1693865 | 2849.65 | Model Group:vliesgevel A:2175042
2317175 | 879.488 | Model Group:vliesgevel C:2317233
2317176 | 2333 | Model Group:vliesgevel C:2317233
2317181 | 2299.5 | Model Group:vliesgevel C:2317233
2317184 | 1128.23 | Model Group:vliesgevel C:2317233
2317185 | 2299.5 | Model Group:vliesgevel C:2317233
2317188 | 1128.23 | Model Group:vliesgevel C:2317233
2317189 | 2299.5 | Model Group:vliesgevel C:2317233
2317192 | 1059.6 | Model Group:vliesgevel C:2317233
2317193 | 2299.5 | Model Group:vliesgevel C:2317233
2317201 | 1200 | Model Group:vliesgevel C:2317233
2317202 | 879.488 | Model Group:vliesgevel C:2317233
2317203 | 1094.73 | Model Group:vliesgevel C:2317233
2317204 | 1094.73 | Model Group:vliesgevel C:2317233
2317205 | 1094.73 | Model Group:vliesgevel C:2317233
2317206 | 1094.73 | Model Group:vliesgevel C:2317233
2317207 | 992.604 | Model Group:vliesgevel C:2317233
2317208 | 1133 | Model Group:vliesgevel C:2317233
2317209 | 1133 | Model Group:vliesgevel C:2317233
2317210 | 1133 | Model Group:vliesgevel C:2317233
2317211 | 1133 | Model Group:vliesgevel C:2317233
2317212 | 1133 | Model Group:vliesgevel C:2317233
2317220 | 2635.22 | Model Group:vliesgevel C:2317233
2317221 | 879.488 | Model Group:vliesgevel C:2317233
2317222 | 1094.73 | Model Group:vliesgevel C:2317233
2317223 | 1094.73 | Model Group:vliesgevel C:2317233
2317224 | 1094.73 | Model Group:vliesgevel C:2317233
2317225 | 992.604 | Model Group:vliesgevel C:2317233
2317226 | 2841.7 | Model Group:vliesgevel C:2317233
2317227 | 2760.84 | Model Group:vliesgevel C:2317233
2317228 | 2679.99 | Model Group:vliesgevel C:2317233
2317235 | 3106.82 | Model Group:vliesgevel C:2317233
2317236 | 2400 | Model Group:vliesgevel C:2317233
2317237 | 1200 | Model Group:vliesgevel C:2317233
2317238 | 3003.41 | Model Group:vliesgevel C:2317233
2317239 | 1062.49 | Model Group:vliesgevel C:2317233
2317240 | 1097.71 | Model Group:vliesgevel C:2317233
2317241 | 1097.71 | Model Group:vliesgevel C:2317233
2317242 | 949.066 | Model Group:vliesgevel C:2317233
2317243 | 1097.71 | Model Group:vliesgevel C:2317233
2317244 | 1097.71 | Model Group:vliesgevel C:2317233
2317245 | 1094.73 | Model Group:vliesgevel C:2317233
2317246 | 2922.56 | Model Group:vliesgevel C:2317233

# IfcMember: Rectangular Mullion:32_CWM_067x114 (108)
Type - PredefinedType: MULLION; Material: RBM_i2_binnenkozijn
Type - Pset_MemberCommon - IsExternal: no; Reference: 32_CWM_067x114
Type - Pset_ProductRequirements - Category: Curtain Wall Mullions
Type - Pset_QuantityTakeOff - Reference: 32_CWM_067x114
Pset_MemberCommon - IsExternal: yes
Name (Rectangular Mullion:32_CWM_067x114:...) | In | Span (mm) | Group
1745529 | 00 begane grond | 2211.17 | Model Group:Vliesgevel B:2773624
1745530 | 00 begane grond | 2177.67 | Model Group:Vliesgevel B:2773624
1748685 | 00 begane grond | 2144.17 | Model Group:Vliesgevel B:2773624
2530423 | 00 begane grond | 1165.92 | Model Group:Vliesgevel B:2773624
2532656 | 00 begane grond | 1290.67 | Model Group:Vliesgevel B:2773624
2532657 | 00 begane grond | 1832.67 | Model Group:Vliesgevel B:2773624
2532658 | 00 begane grond | 2177.67 | Model Group:Vliesgevel B:2773624
2532659 | 00 begane grond | 820 | Model Group:Vliesgevel B:2773624
2532660 | 00 begane grond | 1290.67 | Model Group:Vliesgevel B:2773624
2532661 | 00 begane grond | 2007.36 | Model Group:Vliesgevel B:2773624
2532662 | 00 begane grond | 1098.92 | Model Group:Vliesgevel B:2773624
2532663 | 00 begane grond | 1202.39 | Model Group:Vliesgevel B:2773624
2533105 | 00 begane grond | 1199.3 | Model Group:Vliesgevel B:2773624
2533106 | 00 begane grond | 1175.38 | Model Group:Vliesgevel B:2773624
2533510 | 00 begane grond | 786.5 | Model Group:Vliesgevel B:2773624
2533511 | 00 begane grond | 1357.67 | Model Group:Vliesgevel B:2773624
2533512 | 00 begane grond | 1098.92 | Model Group:Vliesgevel B:2773624
2533513 | 00 begane grond | 1202.39 | Model Group:Vliesgevel B:2773624
2533514 | 00 begane grond | 786.5 | Model Group:Vliesgevel B:2773624
2534488 | 00 begane grond | 1169.01 | Model Group:Vliesgevel B:2773624
2534489 | 00 begane grond | 1205.77 | Model Group:Vliesgevel B:2773624
2534490 | 00 begane grond | 1172.27 | Model Group:Vliesgevel B:2773624
2534491 | 00 begane grond | 1172.27 | Model Group:Vliesgevel B:2773624
2534493 | 00 begane grond | 2144.17 | Model Group:Vliesgevel B:2773624
2534494 | 00 begane grond | 1290.67 | Model Group:Vliesgevel B:2773624
2534495 | 00 begane grond | 786.5 | Model Group:Vliesgevel B:2773624
2534496 | 00 begane grond | 2092.75 | Model Group:Vliesgevel B:2773624
2535008 | 00 begane grond | 1205.56 | Model Group:Vliesgevel B:2773624
2535010 | 00 begane grond | 1196.14 | Model Group:Vliesgevel B:2773624
2535011 | 00 begane grond | 1196.14 | Model Group:Vliesgevel B:2773624
2535014 | 00 begane grond | 1290.67 | Model Group:Vliesgevel B:2773624
2535015 | 00 begane grond | 786.5 | Model Group:Vliesgevel B:2773624
2535016 | 00 begane grond | 1919.79 | Model Group:Vliesgevel B:2773624
1745993 | 00 begane grond | 833.5
1745994 | 00 begane grond | 800
1746000 | 00 begane grond | 833.5
1746001 | 00 begane grond | 800
1746002 | 00 begane grond | 833.5
1746007 | 00 begane grond | 2400
1746008 | 00 begane grond | 2266
1746009 | 00 begane grond | 2266
1746010 | 00 begane grond | 2266
1766038 | 00 begane grond | 833.5
1766039 | 00 begane grond | 2266
1766175 | 00 begane grond | 1633.5
1766178 | 00 begane grond | 867
1766179 | 00 begane grond | 2400
1766180 | 00 begane grond | 2333
1766182 | 00 begane grond | 2266
1766185 | 00 begane grond | 833.5
1766186 | 00 begane grond | 2266
1772881 | 02 tweede verdieping | 2400 | Model Group:32_dubbele deur:2147310
1772882 | 02 tweede verdieping | 2400 | Model Group:32_dubbele deur:2147310
1773055 | 02 tweede verdieping | 1433 | Model Group:32_dubbele deur:2147310
1820737 | 00 begane grond | 655.45 | Model Group:32_kozijn_meterkast:1986720
1820739 | 00 begane grond | 1933 | Model Group:32_kozijn_meterkast:1986720
1820740 | 00 begane grond | 1933 | Model Group:32_kozijn_meterkast:1986720
1820850 | 00 begane grond | 624.55 | Model Group:32_kozijn_meterkast:1986720
2287264 | 01 eerste verdieping | 1400 | Model Group:H07:2287249
2287265 | 01 eerste verdieping | 1400 | Model Group:H07:2287249
2362235 | 00 begane grond | 655.45 | Model Group:H06:2017390
2362236 | 00 begane grond | 2333 | Model Group:H06:2017390
2362237 | 00 begane grond | 2333 | Model Group:H06:2017390
2362240 | 00 begane grond | 624.55 | Model Group:H06:2017390
2760788 | 00 begane grond | 1200 | Model Group:H08:2161338
2760789 | 00 begane grond | 1200 | Model Group:H08:2161338
2760798 | 00 begane grond | 1600 | Model Group:H08:2161338
2760799 | 00 begane grond | 1600 | Model Group:H08:2161338
2760808 | 00 begane grond | 1400 | Model Group:H08:2161338
2760809 | 00 begane grond | 1400 | Model Group:H08:2161338
2760818 | 00 begane grond | 1400 | Model Group:H08:2161338
2760819 | 00 begane grond | 1400 | Model Group:H08:2161338
2760828 | 00 begane grond | 1200 | Model Group:H08:2161338
2760829 | 00 begane grond | 1200 | Model Group:H08:2161338
2760838 | 00 begane grond | 1400 | Model Group:H08:2161338
2760839 | 00 begane grond | 1400 | Model Group:H08:2161338
2760848 | 00 begane grond | 1600 | Model Group:H08:2161338
2760849 | 00 begane grond | 1600 | Model Group:H08:2161338
2760858 | 00 begane grond | 1800 | Model Group:H08:2161338
2760859 | 00 begane grond | 1800 | Model Group:H08:2161338
2760868 | 00 begane grond | 1600 | Model Group:H08:2161338
2760869 | 00 begane grond | 1600 | Model Group:H08:2161338
2760878 | 00 begane grond | 1400 | Model Group:H08:2161338
2760879 | 00 begane grond | 1400 | Model Group:H08:2161338
2760888 | 00 begane grond | 1600 | Model Group:H08:2161338
2760889 | 00 begane grond | 1600 | Model Group:H08:2161338
2761303 | 02 tweede verdieping | 1200 | Model Group:H09:1979223
2761304 | 02 tweede verdieping | 1200 | Model Group:H09:1979223
2761313 | 02 tweede verdieping | 1200 | Model Group:H09:1979223
2761314 | 02 tweede verdieping | 1200 | Model Group:H09:1979223
2763739 | 02 tweede verdieping | 1600 | Model Group:H10:2055879
2763740 | 02 tweede verdieping | 1600 | Model Group:H10:2055879
2763749 | 02 tweede verdieping | 1400 | Model Group:H10:2055879
2763750 | 02 tweede verdieping | 1400 | Model Group:H10:2055879
2763759 | 02 tweede verdieping | 1400 | Model Group:H10:2055879
2763760 | 02 tweede verdieping | 1400 | Model Group:H10:2055879
2763769 | 02 tweede verdieping | 1600 | Model Group:H10:2055879
2763770 | 02 tweede verdieping | 1600 | Model Group:H10:2055879
2763779 | 02 tweede verdieping | 1600 | Model Group:H10:2055879
2763780 | 02 tweede verdieping | 1600 | Model Group:H10:2055879
2763789 | 02 tweede verdieping | 1600 | Model Group:H10:2055879
2763790 | 02 tweede verdieping | 1600 | Model Group:H10:2055879
2764320 | 02 tweede verdieping | 1600 | Model Group:H11:2764105
2764321 | 02 tweede verdieping | 1600 | Model Group:H11:2764105
2764330 | 02 tweede verdieping | 1600 | Model Group:H11:2764105
2764331 | 02 tweede verdieping | 1600 | Model Group:H11:2764105
2764340 | 02 tweede verdieping | 1600 | Model Group:H11:2764105
2764341 | 02 tweede verdieping | 1600 | Model Group:H11:2764105

# IfcMember: Rectangular Mullion:dakbalk_80x160 (28)
In: 03 dak
Type - PredefinedType: MULLION; Material: Staal
Type - Pset_MemberCommon - IsExternal: no; Reference: dakbalk_80x160
Type - Pset_ProductRequirements - Category: Curtain Wall Mullions
Type - Pset_QuantityTakeOff - Reference: dakbalk_80x160
Pset_MemberCommon - IsExternal: yes
Name (Rectangular Mullion:dakbalk_80x160:...) | Span (mm)
2777961 | 3454.18
2777962 | 3282.54
2777963 | 3002.74
2777964 | 2722.94
2777965 | 2443.14
2778003 | 1992.09
2778011 | 3116.65
2778025 | 2163.35
2778029 | 2739.28
2778039 | 3679.08
2779122 | 2554.4
2779166 | 1883.6
2781827 | 1182.44
2777926 | 3113.53
2777927 | 4517.87
2777928 | 4795.45
2777929 | 4961.57
2777930 | 5675.57
2777931 | 6103.02
2777932 | 6530.4
2777933 | 6448.29
2777934 | 2256.63
2777935 | 2705.15
2777936 | 3153.58
2777972 | 3573.82
2778046 | 5128
2778193 | 6957.74
2780549 | 3078.76

# IfcMember: Rectangular Mullion:kolom rond 90 (20)
Type - PredefinedType: MULLION; Material: Staal
Type - Pset_MemberCommon - IsExternal: no; Reference: kolom rond 90
Type - Pset_ProductRequirements - Category: Curtain Wall Mullions
Type - Pset_QuantityTakeOff - Reference: kolom rond 90
Pset_MemberCommon - IsExternal: yes
Name (Rectangular Mullion:kolom rond 90:...) | In | Span (mm)
2779022 | 01 eerste verdieping | 3590.76
2779031 | 01 eerste verdieping | 4084.09
2779034 | 01 eerste verdieping | 3957.34
2779037 | 01 eerste verdieping | 3830.87
2779040 | 01 eerste verdieping | 3702.84
2779043 | 01 eerste verdieping | 4165.72
2779357 | 01 eerste verdieping | 2363.76
2779358 | 01 eerste verdieping | 2485.95
2779378 | 01 eerste verdieping | 2394.5
2779369 | 01 eerste verdieping | 2644
2779371 | 01 eerste verdieping | 2892.42
2779372 | 01 eerste verdieping | 2768.24
2780049 | 02 tweede verdieping | 2118.59
2780050 | 02 tweede verdieping | 1997.85
2780051 | 02 tweede verdieping | 1877.19
2780052 | 02 tweede verdieping | 1756.72
2780071 | 02 tweede verdieping | 1632.84
2780055 | 02 tweede verdieping | 2494.51
2780066 | 02 tweede verdieping | 2320.82
2780067 | 02 tweede verdieping | 2200.04

# IfcMember: Stringer:RBM_trapboom hout_300x50 (4)
Type - PredefinedType: STRINGER
Material: traphout
Pset_MemberCommon - IsExternal: no; Reference: RBM_trapboom hout_300x50
Pset_ProductRequirements - Category: Supports
Pset_QuantityTakeOff - Reference: RBM_trapboom hout_300x50
Name (Assembled Stair:Stair:...) | In | Slope (deg)
1659339 Stringer 1 | 01 eerste verdieping | 36.6743
1659339 Stringer 2 | 01 eerste verdieping | 36.6743
1742392 Stringer 1 | 00 begane grond | 90
1742392 Stringer 2 | 00 begane grond | 42.2737

# IfcMember: Stringer:Stringer - vluchttrap (11)
Type - PredefinedType: STRINGER
Material: <Unnamed>
Pset_MemberCommon - IsExternal: no; Reference: Stringer - vluchttrap
Pset_ProductRequirements - Category: Supports
Pset_QuantityTakeOff - Reference: Stringer - vluchttrap
Name (Assembled Stair:Stair:...) | In | Slope (deg)
2174468 Stringer 1 | -1 kelder | 84.09 | Group: Model Group:trap naar kelder:2174486
2174468 Stringer 2 | -1 kelder | 28.7617 | Group: Model Group:trap naar kelder:2174486
2174468 Stringer 3 | -1 kelder | 0 | Group: Model Group:trap naar kelder:2174486
2174468 Stringer 4 | -1 kelder | 0 | Group: Model Group:trap naar kelder:2174486
2451970 Stringer 1 | 00 begane grond | 90
2451970 Stringer 2 | 00 begane grond | 25.407
2451970 Stringer 3 | 00 begane grond | 0
2451970 Stringer 4 | 00 begane grond | 0
2451970 Stringer 5 | 00 begane grond | 0
2451970 Stringer 6 | 00 begane grond | 0
2451970 Stringer 7 | 00 begane grond | 0

# IfcOpeningElement: Opening (50)
Name | In | Reference | sets with these values | Category
Basic Wall:22_hsb_binnenwand_gips_318,5mm:1641471:1 | 00 begane grond | 22_hsb_binnenwand_gips_318,5mm | 2 | Walls | Pset_ElementShading - Roughness: 304.8 mm
2 x Basic Wall:22_hsb_binnenwand_gips_318,5mm:1641471 | 00 begane grond | NLRS_32_CW_Ontwerpkozijn 067x114 binnen | 2 | Walls | Pset_ManufacturerTypeInformation - Manufacturer: ITANNEX
Basic Wall:22_WA_metalstud_binnenwand_100mm:2391560 | 01 eerste verdieping
2 x Basic Wall:22_hsb_binnenwand_gips_318,5mm:1641685 | 00 begane grond | 22_hsb_binnenwand_gips_318,5mm | 2 | Rectangular Straight Wall Opening | Pset_ElementShading - Roughness: 304.8 mm
Basic Wall:21_RBM_WA_hsb_270mm - geïsoleerd:1643321 | 00 begane grond | NLRS_32_CW_Ontwerpkozijn 067x114 | 2 | Walls | Pset_ManufacturerTypeInformation - Manufacturer: ITANNEX
Basic Wall:22_hsb_binnenwand_gips_318,5mm:1653860 | 02 tweede verdieping | NLRS_32_CW_Ontwerpkozijn 067x114 binnen | 2 | Walls | Pset_ManufacturerTypeInformation - Manufacturer: ITANNEX
Basic Wall:22_hsb_binnenwand_gips_318,5mm:1653861 | 01 eerste verdieping | enkel_gen_bxh 930x2315 | 2 | Doors
Basic Wall:22_hsb_binnenwand_gips_318,5mm:1653861 | 01 eerste verdieping | enkel_gen_bxh 880x2315 | 2 | Doors
 | 02 tweede verdieping | RBM_23_FL_houten kanaalplaat-320mm | 2 | Floors | Pset_ElementShading - Roughness: 304.8 mm
2 x Basic Wall:22_WA_metalstud_binnenwand_100mm:1657880 | 01 eerste verdieping | enkel_gen_bxh 980x2315 | 2 | Doors
 | 01 eerste verdieping | RBM_23_FL_underlayment 19 mm | 2 | Floors | Pset_ElementShading - Roughness: 304.8 mm
Basic Wall:22_hsb_binnenwand_gips_318,5mm:1660133 | 01 eerste verdieping | enkel_gen_bxh 930x2315 | 2 | Doors
Basic Wall:22_hsb_binnenwand_gips_318,5mm:1660133 | 01 eerste verdieping | enkel_gen_bxh 880x2315 | 2 | Doors
Basic Wall:22_WA_metalstud_binnenwand_100mm:1749211 | 01 eerste verdieping
Basic Wall:22_WA_metalstud_binnenwand_100mm:1658055 | 01 eerste verdieping
Basic Wall:22_WA_metalstud_binnenwand_100mm:1657975 | 01 eerste verdieping
4 x Basic Wall:22_WA_metalstud_binnenwand_100mm:1657880 | 01 eerste verdieping
Basic Wall:22_WA_metalstud_binnenwand_100mm:1657769 | 00 begane grond
Basic Wall:22_WA_metalstud_binnenwand_100mm:1657728 | 00 begane grond
2 x Basic Wall:22_hsb_binnenwand_gips_318,5mm:1641685 | 00 begane grond
Basic Wall:21_RBM_WA_hsb_270mm - geïsoleerd:1778975 | 00 begane grond | NLRS_31_CW_Ontwerpkozijn 067x114 | 2 | Walls | Pset_ManufacturerTypeInformation - Manufacturer: ITANNEX
3 x Basic Wall:21_RBM_WA_hsb_270mm_ rockpanel:1886505 | 02 tweede verdieping | NLRS_31_CW_Ontwerpkozijn 067x114 2 | 2 | Walls | Pset_ManufacturerTypeInformation - Manufacturer: ITANNEX
3 x Basic Wall:21_RBM_WA_hsb_270mm_ rockpanel:1886505 | 02 tweede verdieping | NLRS_31_CW_hsb rek 63x196mm h.o.h. 800mm | 2 | Walls | Pset_ManufacturerTypeInformation - Manufacturer: ITANNEX
Basic Wall:21_RBM_WA_hsb_270mm_houten bekleding:1886670 | 00 begane grond | NLRS_31_CW_Ontwerpkozijn 067x114 | 2 | Walls | Pset_ManufacturerTypeInformation - Manufacturer: ITANNEX
2 x Basic Wall:21_RBM_WA_hsb_270mm_houten bekleding:1887040 | 01 eerste verdieping | NLRS_31_CW_hsb rek 63x196mm h.o.h. 800mm | 2 | Walls | Pset_ManufacturerTypeInformation - Manufacturer: ITANNEX
2 x Basic Wall:21_RBM_WA_hsb_270mm_houten bekleding:1887040 | 01 eerste verdieping | NLRS_31_CW_Ontwerpkozijn 067x114 2 | 2 | Walls | Pset_ManufacturerTypeInformation - Manufacturer: ITANNEX
Basic Wall:21_RBM_WA_hsb_270mm_ rockpanel:1887983 | 00 begane grond | NLRS_31_CW_Ontwerpkozijn 067x114 | 2 | Walls | Pset_ManufacturerTypeInformation - Manufacturer: ITANNEX
Basic Wall:21_RBM_WA_hsb_270mm_ rockpanel:1888420 | 00 begane grond | NLRS_31_CW_Ontwerpkozijn 067x114 | 2 | Walls | Pset_ManufacturerTypeInformation - Manufacturer: ITANNEX
Basic Wall:21_RBM_WA_hsb_270mm_ rockpanel:1888480 | 02 tweede verdieping | NLRS_31_CW_Ontwerpkozijn 067x114 | 2 | Walls | Pset_ManufacturerTypeInformation - Manufacturer: ITANNEX
Basic Wall:22_hsb_binnenwand_gips_318,5mm:1970625 | 00 begane grond | NLRS_32_CW_Ontwerpkozijn 067x114 binnen | 2 | Walls | Pset_ManufacturerTypeInformation - Manufacturer: ITANNEX
Basic Wall:21_RBM_WA_hsb_270mm_ rockpanel:2454753 | 02 tweede verdieping | NLRS_31_CW_Ontwerpkozijn 067x114 | 2 | Walls | Pset_ManufacturerTypeInformation - Manufacturer: ITANNEX
 | 01 eerste verdieping | RBM_23_FL_Fermacell_zwevende_dekvloer | 2 | Floors | Pset_ElementShading - Roughness: 304.8 mm
Floor:RBM_23_FL_Fermacell_zwevende_dekvloer:2631502:2 | 01 eerste verdieping | RBM_23_FL_Fermacell_zwevende_dekvloer | 2 | Floors | Pset_ElementShading - Roughness: 304.8 mm
Basic Wall:21_RBM_WA_dakrand/pas strook_rockpanel:2515202 | 02 tweede verdieping | 21_RBM_WA_dakrand/pas strook_rockpanel | 2 | <Sketch> | Pset_ElementShading - Roughness: 304.8 mm
Basic Wall:21_RBM_WA_dakrand/pas strook_rockpanel:2682410 | 03 dak | Vliesgevel C | 2 | Walls | Pset_ManufacturerTypeInformation - Manufacturer: ITANNEX
Basic Wall:21_RBM_WA_hsb_270mm_houten bekleding:2747179 | 00 begane grond | vliesgevel A | 2 | Walls | Pset_ManufacturerTypeInformation - Manufacturer: ITANNEX
Basic Wall:22_hsb_270 passtrook + gips:2752812 | 02 tweede verdieping | NLRS_32_CW_Ontwerpkozijn 067x114 binnen | 2 | Walls | Pset_ManufacturerTypeInformation - Manufacturer: ITANNEX

# IfcPlate: System Panel:31_CWP_glas_1 (26)
In: 00 begane grond
Type - PredefinedType: CURTAIN_PANEL; Classification: 31.11 buitenwandopeningen; niet gevuld, daglichtopeningen (NL/SfB); Material: o1_glas
Type - Pset_ManufacturerTypeInformation - Manufacturer: ITANNEX
Type - Pset_PlateCommon - IsExternal: no; Reference: 31_CWP_glas_1
Type - Pset_ProductRequirements - Category: Curtain Panels
Type - Pset_QuantityTakeOff - Reference: 31_CWP_glas_1
Pset_PlateCommon - IsExternal: yes
Name (System Panel:31_CWP_glas_1:...) | Group
1692367 | Model Group:vliesgevel A:2175042
1693517 | Model Group:vliesgevel A:2175042
1693751 | Model Group:vliesgevel A:2175042
1693752 | Model Group:vliesgevel A:2175042
1693753 | Model Group:vliesgevel A:2175042
1693754 | Model Group:vliesgevel A:2175042
1693841 | Model Group:vliesgevel A:2175042
1693842 | Model Group:vliesgevel A:2175042
1693843 | Model Group:vliesgevel A:2175042
1693844 | Model Group:vliesgevel A:2175042
2317174 | Model Group:vliesgevel C:2317233
2317183 | Model Group:vliesgevel C:2317233
2317187 | Model Group:vliesgevel C:2317233
2317191 | Model Group:vliesgevel C:2317233
2317195 | Model Group:vliesgevel C:2317233
2317196 | Model Group:vliesgevel C:2317233
2317197 | Model Group:vliesgevel C:2317233
2317198 | Model Group:vliesgevel C:2317233
2317199 | Model Group:vliesgevel C:2317233
2317200 | Model Group:vliesgevel C:2317233
2317214 | Model Group:vliesgevel C:2317233
2317215 | Model Group:vliesgevel C:2317233
2317216 | Model Group:vliesgevel C:2317233
2317217 | Model Group:vliesgevel C:2317233
2317218 | Model Group:vliesgevel C:2317233
2317219 | Model Group:vliesgevel C:2317233

# IfcPlate: System Panel:31_CWP_glas_2 (23)
Type - PredefinedType: CURTAIN_PANEL; Material: o1_glas
Type - Pset_PlateCommon - IsExternal: no; Reference: 31_CWP_glas_2
Type - Pset_ProductRequirements - Category: Curtain Panels
Type - Pset_QuantityTakeOff - Reference: 31_CWP_glas_2
Pset_PlateCommon - IsExternal: yes
Name (System Panel:31_CWP_glas_2:...) | In | Group
2287267 | 01 eerste verdieping | Model Group:H07:2287249
2760791 | 00 begane grond | Model Group:H08:2161338
2760801 | 00 begane grond | Model Group:H08:2161338
2760811 | 00 begane grond | Model Group:H08:2161338
2760821 | 00 begane grond | Model Group:H08:2161338
2760831 | 00 begane grond | Model Group:H08:2161338
2760841 | 00 begane grond | Model Group:H08:2161338
2760851 | 00 begane grond | Model Group:H08:2161338
2760861 | 00 begane grond | Model Group:H08:2161338
2760871 | 00 begane grond | Model Group:H08:2161338
2760881 | 00 begane grond | Model Group:H08:2161338
2760891 | 00 begane grond | Model Group:H08:2161338
2761306 | 02 tweede verdieping | Model Group:H09:1979223
2761316 | 02 tweede verdieping | Model Group:H09:1979223
2763742 | 02 tweede verdieping | Model Group:H10:2055879
2763752 | 02 tweede verdieping | Model Group:H10:2055879
2763762 | 02 tweede verdieping | Model Group:H10:2055879
2763772 | 02 tweede verdieping | Model Group:H10:2055879
2763782 | 02 tweede verdieping | Model Group:H10:2055879
2763792 | 02 tweede verdieping | Model Group:H10:2055879
2764323 | 02 tweede verdieping | Model Group:H11:2764105
2764333 | 02 tweede verdieping | Model Group:H11:2764105
2764343 | 02 tweede verdieping | Model Group:H11:2764105

# IfcPlate: System Panel:32_CWP_glas (14)
In: 00 begane grond
Type - PredefinedType: CURTAIN_PANEL; Material: o1_glas
Type - Pset_PlateCommon - IsExternal: no; Reference: 32_CWP_glas
Type - Pset_ProductRequirements - Category: Curtain Panels
Type - Pset_QuantityTakeOff - Reference: 32_CWP_glas
Pset_PlateCommon - IsExternal: yes
Name (System Panel:32_CWP_glas:...) | Group
1745525 | Model Group:Vliesgevel B:2773624
2534468 | Model Group:Vliesgevel B:2773624
2532248 | Model Group:Vliesgevel B:2773624
2534469 | Model Group:Vliesgevel B:2773624
2532249 | Model Group:Vliesgevel B:2773624
2534730 | Model Group:Vliesgevel B:2773624
2533499 | Model Group:Vliesgevel B:2773624
2534470 | Model Group:Vliesgevel B:2773624
2533500 | Model Group:Vliesgevel B:2773624
2534731 | Model Group:Vliesgevel B:2773624
1745975
1745978
1745980
1766173

# IfcRailing: Railing:NLRS_90_RA_LB_hekwerk panelen_gen (3)
Pset_ProductRequirements - Category: Railings
Pset_QuantityTakeOff - Reference: NLRS_90_RA_LB_hekwerk panelen_gen
Pset_RailingCommon - IsExternal: no; Reference: NLRS_90_RA_LB_hekwerk panelen_gen; Height: 1219.2 mm
Name (Railing:NLRS_90_RA_LB_hekwerk panelen_gen:...) | In | Material
2451973 | 00 begane grond | <Unnamed> (20), h2_staal_gen (6)
2452008 | 00 begane grond | <Unnamed> (86), h2_staal_gen (8)
2452040 | 02 tweede verdieping | <Unnamed> (17), h2_staal_gen (2)
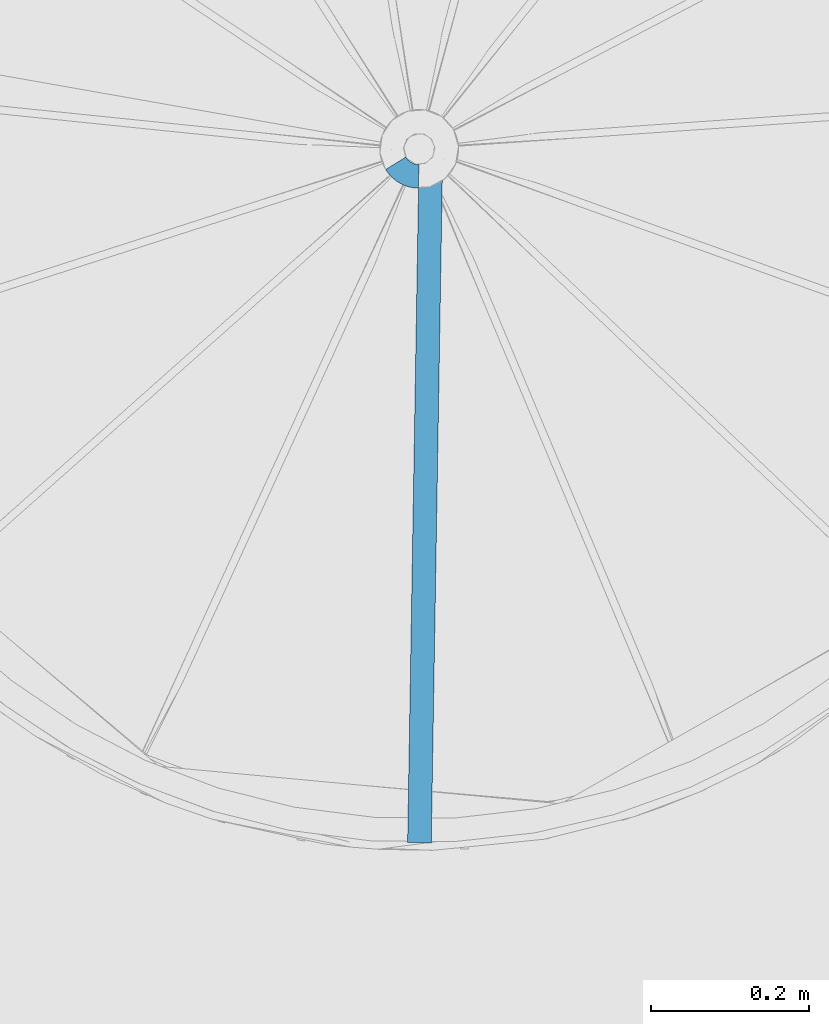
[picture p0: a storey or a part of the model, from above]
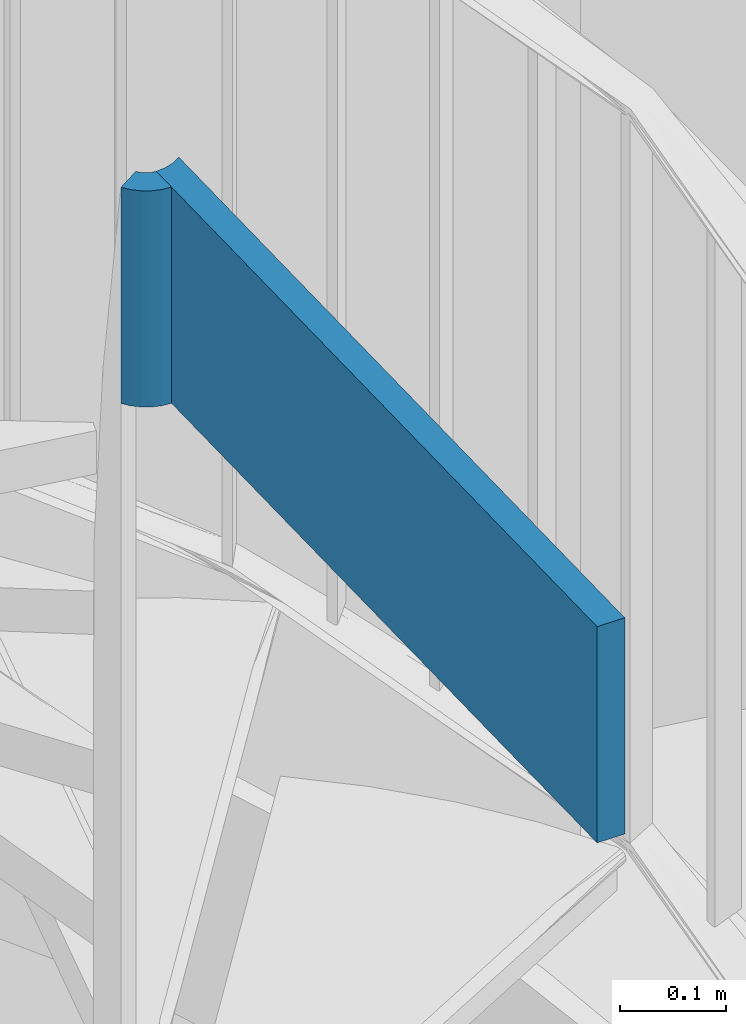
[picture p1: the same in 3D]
Properties of the parts of a building model (IFC2X3), part 2 of 2

# IfcRailing: Railing:NLRS_90_RA_LB_hekwerk panelen_laag (2)
Pset_ProductRequirements - Category: Railings
Pset_QuantityTakeOff - Reference: NLRS_90_RA_LB_hekwerk panelen_laag
Pset_RailingCommon - IsExternal: no; Reference: NLRS_90_RA_LB_hekwerk panelen_laag; Height: 1219.2 mm
Group: Model Group:trap naar kelder:2174486
Name (Railing:NLRS_90_RA_LB_hekwerk panelen_laag:...) | In | Material
2174470 | -1 kelder | <Unnamed> (68), h2_staal_gen (4)
2174483 | 00 begane grond | <Unnamed> (51), h2_staal_gen (2)

# IfcRailing: Railing:NLRS_90_RA_LB_hekwerk spijlen staal, Railing:NLRS_90_RA_LB_hekwerk spijlen staal:2887061
In: 02 tweede verdieping
Material: <Unnamed> (97), h2_staal_gen
Pset_ProductRequirements - Category: Railings
Pset_QuantityTakeOff - Reference: NLRS_90_RA_LB_hekwerk spijlen staal
Pset_RailingCommon - IsExternal: no; Reference: NLRS_90_RA_LB_hekwerk spijlen staal; Height: 1219.2 mm

# IfcRailing: Railing:NLRS_90_RA_LB_hekwerk spijlen staal +trapboom (2)
In: 02 tweede verdieping
Material: <Unnamed> (15), h2_staal_gen (2)
Pset_ProductRequirements - Category: Railings
Pset_QuantityTakeOff - Reference: NLRS_90_RA_LB_hekwerk spijlen staal +trapboom
Pset_RailingCommon - IsExternal: no; Reference: NLRS_90_RA_LB_hekwerk spijlen staal +trapboom; Height: 1219.2 mm
Name (Railing:NLRS_90_RA_LB_hekwerk spijlen staal +trapboom:...)
2871537
2871541

# IfcRailing: Railing:RBM_RA_glasbalustrade (8)
Pset_ProductRequirements - Category: Railings
Pset_QuantityTakeOff - Reference: RBM_RA_glasbalustrade
Pset_RailingCommon - IsExternal: no; Reference: RBM_RA_glasbalustrade; Height: 1066.8 mm
Name (Railing:RBM_RA_glasbalustrade:...) | In | Material
2876911 | 02 tweede verdieping | Glass_RIPO (2), <Unnamed>
2877435 | 00 begane grond | Glass_RIPO, <Unnamed>
2878266 | 02 tweede verdieping | Glass_RIPO, <Unnamed>
2878645 | 02 tweede verdieping | Glass_RIPO, <Unnamed>
2879326 | 02 tweede verdieping | Glass_RIPO, <Unnamed>
2879408 | 02 tweede verdieping | Glass_RIPO, <Unnamed>
2879637 | 02 tweede verdieping | Glass_RIPO, <Unnamed>
2879737 | 02 tweede verdieping | Glass_RIPO, <Unnamed>

# IfcRailing: Railing:RBM_RA_glasbalustrade 02 TRAP (2)
Material: Glass_RIPO, <Unnamed>
Pset_ProductRequirements - Category: Railings
Pset_QuantityTakeOff - Reference: RBM_RA_glasbalustrade 02 TRAP
Pset_RailingCommon - IsExternal: no; Reference: RBM_RA_glasbalustrade 02 TRAP; Height: 1066.8 mm
Name (Railing:RBM_RA_glasbalustrade 02 TRAP:...) | In
2877431 | 00 begane grond
2878579 | 01 eerste verdieping

# IfcRailing: Railing:RBM_RA_handleuning (3)
Material: <Unnamed>
Pset_ProductRequirements - Category: Railings
Pset_QuantityTakeOff - Reference: RBM_RA_handleuning
Pset_RailingCommon - IsExternal: no; Reference: RBM_RA_handleuning; Height: 1066.8 mm
Name (Railing:RBM_RA_handleuning:...) | In
2879164 | 02 tweede verdieping
2879217 | 02 tweede verdieping
2879233 | 01 eerste verdieping

# IfcRoof: Basic Roof:Dak_isolatie goot, Basic Roof:Dak_isolatie goot:2599447
In: 03 dak
Pset_ElementShading - Roughness: 304.8 mm
Pset_ProductRequirements - Category: Roofs
Pset_QuantityTakeOff - Reference: Dak_isolatie goot
Pset_RoofCommon - IsExternal: yes; Reference: Dak_isolatie goot; ProjectedArea: 5.72349 m2; TotalArea: 5.73957 m2

# IfcRoof: Basic Roof:Dak_isolatie+afwerking (2)
Pset_ElementShading - Roughness: 304.8 mm
Pset_ProductRequirements - Category: Roofs
Pset_QuantityTakeOff - Reference: Dak_isolatie+afwerking
Pset_RoofCommon - IsExternal: yes; Reference: Dak_isolatie+afwerking
Name (Basic Roof:Dak_isolatie+afwerking:...) | In | ProjectedArea (m2) | TotalArea (m2)
2319589 | 03 dak | 268.647 | 269.401
2454118 | 02 tweede verdieping | 3.34901 | 3.34901

# IfcRoof: Basic Roof:dakrand, Basic Roof:dakrand:2143979
In: 03 dak
Material: RBM_i2_hout_vuren_gen(1) 600 mm
Pset_ElementShading - Roughness: 304.8 mm
Pset_ProductRequirements - Category: Roofs
Pset_QuantityTakeOff - Reference: dakrand
Pset_RoofCommon - IsExternal: yes; Reference: dakrand; ProjectedArea: 449.378 m2; TotalArea: 9.75975 m2

# IfcRoof: Sloped Glazing:dakbalken (2)
In: 03 dak
Type - Pset_CurtainWallCommon - IsExternal: yes; Reference: dakbalken
Type - Pset_ProductRequirements - Category: Roofs
Type - Pset_QuantityTakeOff - Reference: dakbalken
Pset_RoofCommon - IsExternal: yes; Reference: dakbalken
Name (Sloped Glazing:dakbalken:...) | ProjectedArea (m2)
2777888 | 54.3172
2777893 | 105.253

# IfcSlab: Basic Roof:Dak_isolatie goot, Basic Roof:Dak_isolatie goot:2599447
In: 03 dak
Type - PredefinedType: ROOF
Type - Pset_ElementShading - Roughness: 304.8 mm
Type - Pset_ProductRequirements - Category: Roofs
Type - Pset_QuantityTakeOff - Reference: Dak_isolatie goot
Type - Pset_ReinforcementBarPitchOfSlab - Reference: Dak_isolatie goot
Type - Pset_SlabCommon - IsExternal: yes; Reference: Dak_isolatie goot; ThermalTransmittance: 1000000000000000019884624838656 kg/K/s3
Material: RBM_n7_dakisolatie_80 80 mm
Pset_QuantityTakeOff - sets with these values: 2
Pset_SlabCommon - PitchAngle: 4.29718 deg

# IfcSlab: Basic Roof:Dak_isolatie+afwerking (2)
Type - PredefinedType: ROOF
Type - Pset_ElementShading - Roughness: 304.8 mm
Type - Pset_ProductRequirements - Category: Roofs
Type - Pset_QuantityTakeOff - Reference: Dak_isolatie+afwerking
Type - Pset_ReinforcementBarPitchOfSlab - Reference: Dak_isolatie+afwerking
Type - Pset_SlabCommon - IsExternal: yes; Reference: Dak_isolatie+afwerking; ThermalTransmittance: 1000000000000000019884624838656 kg/K/s3
Material: RBM_n7_dakisolatie_240mm 240 mm
Pset_QuantityTakeOff - sets with these values: 2
Name (Basic Roof:Dak_isolatie+afwerking:...) | In | PitchAngle (deg)
2319589 | 03 dak | 4.29718
2454118 | 02 tweede verdieping | 0

# IfcSlab: Floor:RBM_23_FL_Fermacell_zwevende_dekvloer (2)
In: 01 eerste verdieping
Type - PredefinedType: FLOOR; Material: vloerafwerking pvc 10 mm, Zwevende dekvloer Fermacell 35 mm
Type - Pset_ElementShading - Roughness: 304.8 mm
Type - Pset_ProductRequirements - Category: Floors
Type - Pset_QuantityTakeOff - Reference: RBM_23_FL_Fermacell_zwevende_dekvloer
Type - Pset_ReinforcementBarPitchOfSlab - Description: Fermacell zwevende dekvloer; Reference: RBM_23_FL_Fermacell_zwevende_dekvloer
Type - Pset_SlabCommon - IsExternal: no; Reference: RBM_23_FL_Fermacell_zwevende_dekvloer; ThermalTransmittance: 104.6 kg/K/s3
Pset_SlabCommon - LoadBearing: no; PitchAngle: 0 deg
Name (Floor:RBM_23_FL_Fermacell_zwevende_dekvloer:...)
2631502
2645933

# IfcSlab: Floor:RBM_23_FL_balklaag dak_71x246mm h.o.h.400mm, Floor:RBM_23_FL_balklaag dak_71x246mm h.o.h.400mm:2453909
In: 02 tweede verdieping
Type - PredefinedType: FLOOR; Material: RBM_i2_hout_vuren_gen 246 mm
Type - Pset_ElementShading - Roughness: 304.8 mm
Type - Pset_ProductRequirements - Category: Floors
Type - Pset_QuantityTakeOff - Reference: RBM_23_FL_balklaag dak_71x246mm h.o.h.400mm
Type - Pset_ReinforcementBarPitchOfSlab - Description: vloer, generiek; Reference: RBM_23_FL_balklaag dak_71x246mm h.o.h.400mm
Type - Pset_SlabCommon - IsExternal: no; Reference: RBM_23_FL_balklaag dak_71x246mm h.o.h.400mm; ThermalTransmittance: 0.487805 kg/K/s3
Pset_SlabCommon - LoadBearing: no; PitchAngle: 0 deg

# IfcSlab: Floor:RBM_23_FL_balklaag dak_71x271, h.o.h. 400 (3)
Type - PredefinedType: FLOOR; Material: ISR_Multiplex 18 mm, RBM_i2_hout_vuren_gen 271 mm
Type - Pset_ElementShading - Roughness: 304.8 mm
Type - Pset_ProductRequirements - Category: Floors
Type - Pset_QuantityTakeOff - Reference: RBM_23_FL_balklaag dak_71x271, h.o.h. 400
Type - Pset_ReinforcementBarPitchOfSlab - Description: vloer, generiek; Reference: RBM_23_FL_balklaag dak_71x271, h.o.h. 400
Type - Pset_SlabCommon - IsExternal: no; Reference: RBM_23_FL_balklaag dak_71x271, h.o.h. 400; ThermalTransmittance: 0.442804 kg/K/s3
Pset_SlabCommon - LoadBearing: no; PitchAngle: 0 deg
Name (Floor:RBM_23_FL_balklaag dak_71x271, h.o.h. 400:...) | In
1974393 | 02 tweede verdieping
1977292 | 01 eerste verdieping
2748788 | 01 eerste verdieping

# IfcSlab: Floor:RBM_23_FL_dakisolatie 30 mm (2)
In: 01 eerste verdieping
Type - PredefinedType: FLOOR; Material: RBM_n7_dakisolatie_gen 50 mm
Type - Pset_ElementShading - Roughness: 304.8 mm
Type - Pset_ProductRequirements - Category: Floors
Type - Pset_QuantityTakeOff - Reference: RBM_23_FL_dakisolatie 30 mm
Type - Pset_ReinforcementBarPitchOfSlab - Description: vloer, generiek; Reference: RBM_23_FL_dakisolatie 30 mm
Type - Pset_SlabCommon - IsExternal: no; Reference: RBM_23_FL_dakisolatie 30 mm
Pset_SlabCommon - LoadBearing: no; PitchAngle: 0 deg
Name (Floor:RBM_23_FL_dakisolatie 30 mm:...)
2748825
2749276

# IfcSlab: Floor:RBM_23_FL_dakisolatie 30 mm afschot 15mm/m1, Floor:RBM_23_FL_dakisolatie 30 mm afschot 15mm/m1:2749066
In: 02 tweede verdieping
Type - PredefinedType: FLOOR
Type - Pset_ElementShading - Roughness: 304.8 mm
Type - Pset_ProductRequirements - Category: Floors
Type - Pset_QuantityTakeOff - Reference: RBM_23_FL_dakisolatie 30 mm afschot 15mm/m1
Type - Pset_ReinforcementBarPitchOfSlab - Description: vloer, generiek; Reference: RBM_23_FL_dakisolatie 30 mm afschot 15mm/m1
Type - Pset_SlabCommon - IsExternal: no; Reference: RBM_23_FL_dakisolatie 30 mm afschot 15mm/m1
Pset_SlabCommon - LoadBearing: no; PitchAngle: 0.859372 deg

# IfcSlab: Floor:RBM_23_FL_gewapende druklaag gevlinderd (3)
In: 00 begane grond
Type - PredefinedType: FLOOR; Material: vloerafwerking pvc 10 mm, RBM_f2_beton_ihwg C20-25 80 mm
Type - Pset_ElementShading - Roughness: 304.8 mm
Type - Pset_ProductRequirements - Category: Floors
Type - Pset_QuantityTakeOff - Reference: RBM_23_FL_gewapende druklaag gevlinderd
Type - Pset_ReinforcementBarPitchOfSlab - Description: vloer, generiek; Reference: RBM_23_FL_gewapende druklaag gevlinderd
Type - Pset_SlabCommon - IsExternal: no; Reference: RBM_23_FL_gewapende druklaag gevlinderd; ThermalTransmittance: 11.6222 kg/K/s3
Pset_SlabCommon - LoadBearing: no; PitchAngle: 0 deg
Name (Floor:RBM_23_FL_gewapende druklaag gevlinderd:...)
2793050
2796847
2798566

# IfcSlab: Floor:RBM_23_FL_gewapende druklaag gevlinderd, Floor:RBM_23_FL_gewapende druklaag gevlinderd:2540512
In: 00 begane grond
Type - PredefinedType: FLOOR
Type - Pset_ElementShading - Roughness: 304.8 mm
Type - Pset_ProductRequirements - Category: Floors
Type - Pset_QuantityTakeOff - Reference: RBM_23_FL_gewapende druklaag gevlinderd
Type - Pset_ReinforcementBarPitchOfSlab - Description: vloer, generiek; Reference: RBM_23_FL_gewapende druklaag gevlinderd
Type - Pset_SlabCommon - IsExternal: no; Reference: RBM_23_FL_gewapende druklaag gevlinderd; ThermalTransmittance: 11.6222 kg/K/s3
Pset_SlabCommon - LoadBearing: no; PitchAngle: 0 deg

# IfcSlab: Floor:RBM_23_FL_houten kanaalplaat-320mm (2)
Type - PredefinedType: FLOOR; Material: RBM_i4_multiplex_beplating 320 mm
Type - Pset_ElementShading - Roughness: 304.8 mm
Type - Pset_ProductRequirements - Category: Floors
Type - Pset_QuantityTakeOff - Reference: RBM_23_FL_houten kanaalplaat-320mm
Type - Pset_ReinforcementBarPitchOfSlab - Description: prefab houten kanaalplaatvloer, vrijdragend; Reference: RBM_23_FL_houten kanaalplaat-320mm
Type - Pset_SlabCommon - IsExternal: no; Reference: RBM_23_FL_houten kanaalplaat-320mm; ThermalTransmittance: 0.33125 kg/K/s3
Pset_SlabCommon - LoadBearing: no
Name (Floor:RBM_23_FL_houten kanaalplaat-320mm:...) | In | PitchAngle (deg)
1655074 | 02 tweede verdieping | 0
1733735 | 03 dak | 4.28915

# IfcSlab: Floor:RBM_23_FL_houten vloer-brug (2)
Type - PredefinedType: FLOOR; Material: traphout 50 mm
Type - Pset_ElementShading - Roughness: 304.8 mm
Type - Pset_ProductRequirements - Category: Floors
Type - Pset_QuantityTakeOff - Reference: RBM_23_FL_houten vloer-brug
Type - Pset_ReinforcementBarPitchOfSlab - Description: vloer, generiek; Reference: RBM_23_FL_houten vloer-brug
Type - Pset_SlabCommon - IsExternal: no; Reference: RBM_23_FL_houten vloer-brug; ThermalTransmittance: 2.4 kg/K/s3
Pset_SlabCommon - LoadBearing: no; PitchAngle: 0 deg
Name (Floor:RBM_23_FL_houten vloer-brug:...) | In
1654735 | 01 eerste verdieping
1659754 | 02 tweede verdieping

# IfcSlab: Floor:RBM_23_FL_kanaalplaat-200mm_gen_rsf (2)
In: 00 begane grond
Type - PredefinedType: FLOOR; Material: RBM_f2_beton_prefab_gen 260 mm
Type - Pset_ElementShading - Roughness: 304.8 mm
Type - Pset_ProductRequirements - Category: Floors
Type - Pset_QuantityTakeOff - Reference: RBM_23_FL_kanaalplaat-200mm_gen_rsf
Type - Pset_ReinforcementBarPitchOfSlab - Description: prefab kanaalplaatvloer, vrijdragend; Reference: RBM_23_FL_kanaalplaat-200mm_gen_rsf
Type - Pset_SlabCommon - IsExternal: no; Reference: RBM_23_FL_kanaalplaat-200mm_gen_rsf; ThermalTransmittance: 4.02308 kg/K/s3
Pset_SlabCommon - LoadBearing: no; PitchAngle: 0 deg
Name (Floor:RBM_23_FL_kanaalplaat-200mm_gen_rsf:...)
1655273
2801751

# IfcSlab: Floor:RBM_23_FL_kanaalplaat-260mm+druklaag-80mm, Floor:RBM_23_FL_kanaalplaat-260mm+druklaag-80mm:1655409
In: 00 begane grond
Type - PredefinedType: FLOOR; Material: vloerafwerking pvc 10 mm, RBM_f2_beton_ihwg_gen 60 mm, RBM_f2_beton_ihwg C20-25 70 mm, RBM_f2_beton_prefab_gen 260 mm, RBM_n7_isolatie_EPS 140 mm
Type - Pset_ElementShading - Roughness: 304.8 mm
Type - Pset_ProductRequirements - Category: Floors
Type - Pset_QuantityTakeOff - Reference: RBM_23_FL_kanaalplaat-260mm+druklaag-80mm
Type - Pset_ReinforcementBarPitchOfSlab - Description: prefab kanaalplaatvloer, vrijdragend; Reference: RBM_23_FL_kanaalplaat-260mm+druklaag-80mm
Type - Pset_SlabCommon - IsExternal: no; Reference: RBM_23_FL_kanaalplaat-260mm+druklaag-80mm; ThermalTransmittance: 0.228185 kg/K/s3
Pset_SlabCommon - LoadBearing: no; PitchAngle: 0 deg

# IfcSlab: Floor:RBM_23_FL_kanaalplaat-260mm+druklaag-80mm overbrugging, Floor:RBM_23_FL_kanaalplaat-260mm+druklaag-80mm overbrugging:2235945
In: 00 begane grond
Type - PredefinedType: FLOOR; Material: vloerafwerking pvc 10 mm, RBM_f2_beton_ihwg_gen 80 mm, RBM_n7_isolatie_hsb_245 540 mm, RBM_f2_beton_prefab_gen 260 mm
Type - Pset_ElementShading - Roughness: 304.8 mm
Type - Pset_ProductRequirements - Category: Floors
Type - Pset_QuantityTakeOff - Reference: RBM_23_FL_kanaalplaat-260mm+druklaag-80mm overbrugging
Type - Pset_ReinforcementBarPitchOfSlab - Description: prefab kanaalplaatvloer, vrijdragend; Reference: RBM_23_FL_kanaalplaat-260mm+druklaag-80mm overbrugging
Type - Pset_SlabCommon - IsExternal: no; Reference: RBM_23_FL_kanaalplaat-260mm+druklaag-80mm overbrugging; ThermalTransmittance: 2.98857 kg/K/s3
Pset_SlabCommon - LoadBearing: no; PitchAngle: 0 deg

# IfcSlab: Floor:RBM_23_FL_tempex 690mm (2)
In: 00 begane grond
Type - PredefinedType: FLOOR; Material: RBM_n7_isolatie_hsb_245 560 mm
Type - Pset_ElementShading - Roughness: 304.8 mm
Type - Pset_ProductRequirements - Category: Floors
Type - Pset_QuantityTakeOff - Reference: RBM_23_FL_tempex 690mm
Type - Pset_ReinforcementBarPitchOfSlab - Description: vloer, generiek; Reference: RBM_23_FL_tempex 690mm
Type - Pset_SlabCommon - IsExternal: no; Reference: RBM_23_FL_tempex 690mm
Pset_SlabCommon - LoadBearing: no; PitchAngle: 0 deg
Name (Floor:RBM_23_FL_tempex 690mm:...)
2795189
2799929

# IfcSlab: Floor:RBM_23_FL_tempex 790, Floor:RBM_23_FL_tempex 790:2795876
In: 00 begane grond
Type - PredefinedType: FLOOR; Material: RBM_n7_isolatie_hsb_245 790 mm
Type - Pset_ElementShading - Roughness: 304.8 mm
Type - Pset_ProductRequirements - Category: Floors
Type - Pset_QuantityTakeOff - Reference: RBM_23_FL_tempex 790
Type - Pset_ReinforcementBarPitchOfSlab - Description: vloer, generiek; Reference: RBM_23_FL_tempex 790
Type - Pset_SlabCommon - IsExternal: no; Reference: RBM_23_FL_tempex 790
Pset_SlabCommon - LoadBearing: no; PitchAngle: 0 deg

# IfcSlab: Floor:RBM_23_FL_tempex 800mm, Floor:RBM_23_FL_tempex 800mm:1982200
In: 00 begane grond
Type - PredefinedType: FLOOR; Material: RBM_n7_isolatie_hsb_245 800 mm
Type - Pset_ElementShading - Roughness: 304.8 mm
Type - Pset_ProductRequirements - Category: Floors
Type - Pset_QuantityTakeOff - Reference: RBM_23_FL_tempex 800mm
Type - Pset_ReinforcementBarPitchOfSlab - Description: vloer, generiek; Reference: RBM_23_FL_tempex 800mm
Type - Pset_SlabCommon - IsExternal: no; Reference: RBM_23_FL_tempex 800mm
Pset_SlabCommon - LoadBearing: no; PitchAngle: 0 deg

# IfcSlab: Floor:RBM_23_FL_underlayment 19 mm, Floor:RBM_23_FL_underlayment 19 mm:1659719
In: 01 eerste verdieping
Type - PredefinedType: FLOOR; Material: ISR_Multiplex 19 mm
Type - Pset_ElementShading - Roughness: 304.8 mm
Type - Pset_ProductRequirements - Category: Floors
Type - Pset_QuantityTakeOff - Reference: RBM_23_FL_underlayment 19 mm
Type - Pset_ReinforcementBarPitchOfSlab - Description: vloer, generiek; Reference: RBM_23_FL_underlayment 19 mm
Type - Pset_SlabCommon - IsExternal: no; Reference: RBM_23_FL_underlayment 19 mm
Pset_SlabCommon - LoadBearing: no; PitchAngle: 0 deg

# IfcSlab: Floor:RBM_43_FL_betontegels op dragers (2)
In: 02 tweede verdieping
Type - PredefinedType: FLOOR; Material: RBM_f2_betontegels 30 mm, RBM_n7_isolatie_zwevende dekvloer 20 mm
Type - Pset_ElementShading - Roughness: 304.8 mm
Type - Pset_ProductRequirements - Category: Floors
Type - Pset_QuantityTakeOff - Reference: RBM_43_FL_betontegels op dragers
Type - Pset_ReinforcementBarPitchOfSlab - Description: betontegels op dragers; Reference: RBM_43_FL_betontegels op dragers
Type - Pset_SlabCommon - IsExternal: no; Reference: RBM_43_FL_betontegels op dragers; ThermalTransmittance: 1.66636 kg/K/s3
Pset_SlabCommon - LoadBearing: no; IsExternal: yes; PitchAngle: 0 deg
Name (Floor:RBM_43_FL_betontegels op dragers:...)
2874446
2880596

# IfcSlab: Floor:RBM_43_FL_cementdekvloer-50mm_gen_rsf, Floor:RBM_43_FL_cementdekvloer-50mm_gen_rsf:2319789
In: 00 begane grond
Type - PredefinedType: FLOOR; Material: RBM_f2_beton_ihwg_gen 100 mm
Type - Pset_ElementShading - Roughness: 304.8 mm
Type - Pset_ProductRequirements - Category: Floors
Type - Pset_QuantityTakeOff - Reference: RBM_43_FL_cementdekvloer-50mm_gen_rsf
Type - Pset_ReinforcementBarPitchOfSlab - Description: zandcement dekvloer; Reference: RBM_43_FL_cementdekvloer-50mm_gen_rsf
Type - Pset_SlabCommon - IsExternal: no; Reference: RBM_43_FL_cementdekvloer-50mm_gen_rsf; ThermalTransmittance: 10.46 kg/K/s3
Pset_SlabCommon - LoadBearing: no; PitchAngle: 0 deg

# IfcSlab: Floor:RBM_43_FL_roostervloer (3)
Type - PredefinedType: FLOOR; Material: Roostervloer 50 mm
Type - Pset_ElementShading - Roughness: 304.8 mm
Type - Pset_ProductRequirements - Category: Floors
Type - Pset_QuantityTakeOff - Reference: RBM_43_FL_roostervloer
Type - Pset_ReinforcementBarPitchOfSlab - Description: roostervloer; Reference: RBM_43_FL_roostervloer
Type - Pset_SlabCommon - IsExternal: no; Reference: RBM_43_FL_roostervloer
Pset_SlabCommon - LoadBearing: no; PitchAngle: 0 deg
Name (Floor:RBM_43_FL_roostervloer:...) | In
2876685 | 00 begane grond
2876763 | 00 begane grond
2880514 | 02 tweede verdieping

# IfcStair: Assembled Stair:RBM_ST_houten trap (2)
ShapeType: STRAIGHT_RUN_STAIR
Pset_ProductRequirements - Category: Stairs
Pset_QuantityTakeOff - Reference: RBM_ST_houten trap
Pset_StairCommon - IsExternal: no; Reference: RBM_ST_houten trap
Name (Assembled Stair:Stair:...) | In | NumberOfRiser | NumberOfTreads | RiserHeight (mm) | TreadLength (mm)
1659339 | 01 eerste verdieping | 4 | 4 | 175 | 235
1742392 | 00 begane grond | 16 | 15 | 200 | 220

# IfcStair: Assembled Stair:Vluchttrap (2)
ShapeType: SPIRAL_STAIR
Pset_ProductRequirements - Category: Stairs
Pset_QuantityTakeOff - Reference: Vluchttrap
Pset_StairCommon - IsExternal: no; Reference: Vluchttrap; RiserHeight: 200 mm
Name (Assembled Stair:Stair:...) | In | NumberOfRiser | NumberOfTreads | TreadLength (mm)
2174468 | -1 kelder | 20 | 19 | 185 | Group: Model Group:trap naar kelder:2174486
2451970 | 00 begane grond | 18 | 17 | 260

# IfcStair: Assembled Stair:Vluchttrap staal, Assembled Stair:Stair:2870841
In: 02 tweede verdieping
ShapeType: STRAIGHT_RUN_STAIR
Pset_ProductRequirements - Category: Stairs
Pset_QuantityTakeOff - Reference: Vluchttrap staal
Pset_StairCommon - IsExternal: yes; Reference: Vluchttrap staal; NumberOfRiser: 8; NumberOfTreads: 7; RiserHeight: 205.833 mm; TreadLength: 185 mm

# IfcStairFlight: Non-Monolithic Run:40 mm persrooster, Assembled Stair:Stair:2870841 Run 1
In: 02 tweede verdieping
Type - Pset_ProductRequirements - Category: Runs
Type - Pset_QuantityTakeOff - Reference: 40 mm persrooster
Type - Pset_StairFlightCommon - NosingLength: 0 mm; Reference: 40 mm persrooster
NumberOfRiser: 8; NumberOfTreads: 7; RiserHeight: 0.675306 mm; TreadLength: 0.606955 mm; Material: <Unnamed> (7)
Pset_StairFlightCommon - NumberOfRiser: 8; NumberOfTreads: 7; RiserHeight: 205.833 mm; TreadLength: 185 mm; TreadLengthAtOffset: 185 mm; TreadLengthAtInnerSide: 185 mm

# IfcStairFlight: Non-Monolithic Run:50mm Tread 13mm Riser (2)
Type - PredefinedType: SPIRAL
Type - Pset_ProductRequirements - Category: Runs
Type - Pset_QuantityTakeOff - Reference: 50mm Tread 13mm Riser
Type - Pset_StairFlightCommon - Reference: 50mm Tread 13mm Riser; NosingLength: 0 mm
RiserHeight: 0.656168 mm
Pset_StairFlightCommon - RiserHeight: 200 mm
Name (Assembled Stair:Stair:...) | In | NumberOfRiser = Pset_StairFlightCommon, NumberOfRiser | NumberOfTreads = Pset_StairFlightCommon, NumberOfTreads | TreadLength (mm) | Material | Pset_StairFlightCommon, TreadLength (mm) = TreadLengthAtOffset (mm) = TreadLengthAtInnerSide (mm) | WalkingLineOffset (mm)
2174468 Run 1 | -1 kelder | 20 | 19 | 0.606955 | <Unnamed> (19) | 185 | 1.31234 | Group: Model Group:trap naar kelder:2174486
2451970 Run 1 | 00 begane grond | 18 | 17 | 0.853018 | <Unnamed> (17) | 260 | 1.47638

# IfcStairFlight: Non-Monolithic Run:RBM_ST_samengestelde houten trede (2)
Type - PredefinedType: STRAIGHT
Type - Pset_ProductRequirements - Category: Runs
Type - Pset_QuantityTakeOff - Reference: RBM_ST_samengestelde houten trede
Type - Pset_StairFlightCommon - Reference: RBM_ST_samengestelde houten trede; NosingLength: 25 mm
Name (Assembled Stair:Stair:...) | In | NumberOfRiser = Pset_StairFlightCommon, NumberOfRiser | NumberOfTreads = Pset_StairFlightCommon, NumberOfTreads | RiserHeight (mm) | TreadLength (mm) | Material | Pset_StairFlightCommon, RiserHeight (mm) | Pset_StairFlightCommon, TreadLength (mm) = TreadLengthAtOffset (mm) = TreadLengthAtInnerSide (mm) | WalkingLineOffset (mm)
1659339 Run 1 | 01 eerste verdieping | 4 | 4 | 0.574147 | 0.770997 | traphout (4) | 175 | 235 | 2.29659
1742392 Run 1 | 00 begane grond | 16 | 15 | 0.656168 | 0.721785 | traphout (15) | 200 | 220 | 2.13255

# IfcWall: Basic Wall:20_RBM_WA_HSB_wand-100mm_gevelafwerking (2)
In: 00 begane grond
Type - PredefinedType: STANDARD; Material: Gevelafwerking 30 mm, ISR_Luchtspouw 35 mm, ISR_Luchtspouw 35 mm
Type - Pset_ElementShading - Roughness: 304.8 mm
Type - Pset_ProductRequirements - Category: Walls
Type - Pset_QuantityTakeOff - Reference: 20_RBM_WA_HSB_wand-100mm_gevelafwerking
Type - Pset_ReinforcementBarPitchOfWall - Description: buitenwand, generiek; Reference: 20_RBM_WA_HSB_wand-100mm_gevelafwerking
Type - Pset_WallCommon - IsExternal: no; Reference: 20_RBM_WA_HSB_wand-100mm_gevelafwerking
Pset_WallCommon - ExtendToStructure: no; LoadBearing: no; IsExternal: yes
Name (Basic Wall:20_RBM_WA_HSB_wand-100mm_gevelafwerking:...)
2523123
2745446

# IfcWall: Basic Wall:21_RBM_WA_170mm_geïsoleerde_kantplank, Basic Wall:21_RBM_WA_170mm_geïsoleerde_kantplank:1886998
In: 00 begane grond
Type - PredefinedType: STANDARD; Material: geisoleerde cementvezelplaat 20 mm, RBM_n7_isolatie_resol 150 mm
Type - Pset_ElementShading - Roughness: 304.8 mm
Type - Pset_ProductRequirements - Category: Walls
Type - Pset_QuantityTakeOff - Reference: 21_RBM_WA_170mm_geïsoleerde_kantplank
Type - Pset_ReinforcementBarPitchOfWall - Description: isolatie, resolschuim; Reference: 21_RBM_WA_170mm_geïsoleerde_kantplank
Type - Pset_WallCommon - IsExternal: no; Reference: 21_RBM_WA_170mm_geïsoleerde_kantplank
Pset_WallCommon - ExtendToStructure: no; LoadBearing: no; IsExternal: yes

# IfcWall: Basic Wall:21_RBM_WA_dakrand/pas strook_rockpanel (2)
Type - PredefinedType: STANDARD; Material: gevel antraciet 8 mm, ISR_Luchtspouw 35 mm, ISR_Luchtspouw 35 mm, RBM_n7_isolatie_hsb_270 138 mm
Type - Pset_ElementShading - Roughness: 304.8 mm
Type - Pset_ProductRequirements - Category: Walls
Type - Pset_QuantityTakeOff - Reference: 21_RBM_WA_dakrand/pas strook_rockpanel
Type - Pset_ReinforcementBarPitchOfWall - Description: isolatie, resolschuim; Reference: 21_RBM_WA_dakrand/pas strook_rockpanel
Type - Pset_WallCommon - IsExternal: no; Reference: 21_RBM_WA_dakrand/pas strook_rockpanel
Pset_WallCommon - ExtendToStructure: no; LoadBearing: no; IsExternal: yes
Name (Basic Wall:21_RBM_WA_dakrand/pas strook_rockpanel:...) | In
1888479 | 02 tweede verdieping
2683869 | 03 dak

# IfcWall: Basic Wall:21_RBM_WA_dakrand_houten bekleding, Basic Wall:21_RBM_WA_dakrand_houten bekleding:2731481
In: 03 dak
Type - PredefinedType: STANDARD; Material: Gevelafwerking 30 mm, ISR_Luchtspouw 35 mm, ISR_Luchtspouw 35 mm, RBM_n7_isolatie_hsb_invulling 138 mm
Type - Pset_ElementShading - Roughness: 304.8 mm
Type - Pset_ProductRequirements - Category: Walls
Type - Pset_QuantityTakeOff - Reference: 21_RBM_WA_dakrand_houten bekleding
Type - Pset_ReinforcementBarPitchOfWall - Description: isolatie, resolschuim; Reference: 21_RBM_WA_dakrand_houten bekleding
Type - Pset_WallCommon - IsExternal: no; Reference: 21_RBM_WA_dakrand_houten bekleding
Pset_WallCommon - ExtendToStructure: no; LoadBearing: no; IsExternal: yes

# IfcWall: Basic Wall:21_RBM_WA_dakrand_rockpanel_uitvullen, Basic Wall:21_RBM_WA_dakrand_rockpanel_uitvullen:2735765
In: 03 dak
Type - PredefinedType: STANDARD; Material: gevel antraciet 8 mm, ISR_Luchtspouw 22 mm, ISR_Luchtspouw 35 mm, ISR_Luchtspouw 35 mm, RBM_n7_isolatie_hsb_270 138 mm
Type - Pset_ElementShading - Roughness: 304.8 mm
Type - Pset_ProductRequirements - Category: Walls
Type - Pset_QuantityTakeOff - Reference: 21_RBM_WA_dakrand_rockpanel_uitvullen
Type - Pset_ReinforcementBarPitchOfWall - Description: isolatie, resolschuim; Reference: 21_RBM_WA_dakrand_rockpanel_uitvullen
Type - Pset_WallCommon - IsExternal: no; Reference: 21_RBM_WA_dakrand_rockpanel_uitvullen
Pset_WallCommon - ExtendToStructure: no; LoadBearing: no; IsExternal: yes

# IfcWall: Basic Wall:21_RBM_WA_hsb_270mm_ rockpanel, Basic Wall:21_RBM_WA_hsb_270mm_ rockpanel:1886577
In: 02 tweede verdieping
Type - PredefinedType: STANDARD; Material: gevel antraciet 8 mm, ISR_Luchtspouw 35 mm, ISR_Luchtspouw 35 mm, RBM_n7_isolatie_hsb_270 270 mm, RBM_i4_multiplex_beplating 18 mm
Type - Pset_ElementShading - Roughness: 304.8 mm
Type - Pset_ProductRequirements - Category: Walls
Type - Pset_QuantityTakeOff - Reference: 21_RBM_WA_hsb_270mm_ rockpanel
Type - Pset_ReinforcementBarPitchOfWall - Description: hsb element 196mm, buitenafwerking: osb plaat met wind- en waterkerende folie, binnenwafwerking: osb plaat in het zicht; Reference: 21_RBM_WA_hsb_270mm_ rockpanel
Type - Pset_WallCommon - IsExternal: no; Reference: 21_RBM_WA_hsb_270mm_ rockpanel; ThermalTransmittance: 5.88889 kg/K/s3
Pset_WallCommon - ExtendToStructure: no; LoadBearing: no; IsExternal: yes

# IfcWall: Basic Wall:21_RBM_WA_hsb_270mm_houten bekleding (4)
Type - PredefinedType: STANDARD; Material: Gevelafwerking 30 mm, ISR_Luchtspouw 35 mm, ISR_Luchtspouw 35 mm, RBM_n7_isolatie_hsb_270 270 mm, RBM_i4_multiplex_beplating 18 mm
Type - Pset_ElementShading - Roughness: 304.8 mm
Type - Pset_ProductRequirements - Category: Walls
Type - Pset_QuantityTakeOff - Reference: 21_RBM_WA_hsb_270mm_houten bekleding
Type - Pset_ReinforcementBarPitchOfWall - Description: hsb element 196mm, buitenafwerking: osb plaat met wind- en waterkerende folie, binnenwafwerking: osb plaat in het zicht; Reference: 21_RBM_WA_hsb_270mm_houten bekleding
Type - Pset_WallCommon - IsExternal: no; Reference: 21_RBM_WA_hsb_270mm_houten bekleding; ThermalTransmittance: 5.88889 kg/K/s3
Pset_WallCommon - LoadBearing: no; IsExternal: yes
Name (Basic Wall:21_RBM_WA_hsb_270mm_houten bekleding:...) | In | ExtendToStructure
1653871 | 02 tweede verdieping | no
1886117 | 00 begane grond | yes
1887044 | 01 eerste verdieping | no
2520142 | 00 begane grond | no

# IfcWall: Basic Wall:21_RBM_WA_passtrook_BU_houten bekleding (2)
In: 01 eerste verdieping
Type - PredefinedType: STANDARD; Material: Gevelafwerking 30 mm, ISR_Luchtspouw 35 mm, ISR_Luchtspouw 35 mm, RBM_n7_isolatie_hsb_invulling 138 mm
Type - Pset_ElementShading - Roughness: 304.8 mm
Type - Pset_ProductRequirements - Category: Walls
Type - Pset_QuantityTakeOff - Reference: 21_RBM_WA_passtrook_BU_houten bekleding
Type - Pset_ReinforcementBarPitchOfWall - Description: isolatie, resolschuim; Reference: 21_RBM_WA_passtrook_BU_houten bekleding
Type - Pset_WallCommon - IsExternal: no; Reference: 21_RBM_WA_passtrook_BU_houten bekleding
Pset_WallCommon - ExtendToStructure: no; LoadBearing: no; IsExternal: yes
Name (Basic Wall:21_RBM_WA_passtrook_BU_houten bekleding:...)
1887043
2521709

# IfcWall: Basic Wall:22_WA_hsb-buitenwand_100mm 2, Basic Wall:22_WA_hsb-buitenwand_100mm 2:1771100
In: 00 begane grond
Type - PredefinedType: STANDARD; Material: RBM_n7_isolatie_hsb_100 100 mm
Type - Pset_ElementShading - Roughness: 304.8 mm
Type - Pset_ProductRequirements - Category: Walls
Type - Pset_QuantityTakeOff - Reference: 22_WA_hsb-buitenwand_100mm 2
Type - Pset_ReinforcementBarPitchOfWall - Reference: 22_WA_hsb-buitenwand_100mm 2
Type - Pset_WallCommon - IsExternal: no; Reference: 22_WA_hsb-buitenwand_100mm 2
Pset_QuantityTakeOff - sets with these values: 2
Pset_WallCommon - ExtendToStructure: no; LoadBearing: no

# IfcWallStandardCase: Basic Wall:20_RBM_WA_HSB_wand-100mm_gevelafwerking (7)
Type - PredefinedType: STANDARD; Material: Gevelafwerking 30 mm, ISR_Luchtspouw 35 mm, ISR_Luchtspouw 35 mm
Type - Pset_ElementShading - Roughness: 304.8 mm
Type - Pset_ProductRequirements - Category: Walls
Type - Pset_QuantityTakeOff - Reference: 20_RBM_WA_HSB_wand-100mm_gevelafwerking
Type - Pset_ReinforcementBarPitchOfWall - Description: buitenwand, generiek; Reference: 20_RBM_WA_HSB_wand-100mm_gevelafwerking
Type - Pset_WallCommon - IsExternal: no; Reference: 20_RBM_WA_HSB_wand-100mm_gevelafwerking
Pset_WallCommon - ExtendToStructure: no; LoadBearing: no; IsExternal: yes
Name (Basic Wall:20_RBM_WA_HSB_wand-100mm_gevelafwerking:...) | In
2511620 | 00 begane grond
2514147 | 00 begane grond
2514630 | 00 begane grond
2514782 | 00 begane grond
2515039 | 00 begane grond
2516713 | 01 eerste verdieping
2526738 | 00 begane grond

# IfcWallStandardCase: Basic Wall:21_RBM_WA_170mm_geïsoleerde_kantplank (13)
In: 00 begane grond
Type - PredefinedType: STANDARD; Material: geisoleerde cementvezelplaat 20 mm, RBM_n7_isolatie_resol 150 mm
Type - Pset_ElementShading - Roughness: 304.8 mm
Type - Pset_ProductRequirements - Category: Walls
Type - Pset_QuantityTakeOff - Reference: 21_RBM_WA_170mm_geïsoleerde_kantplank
Type - Pset_ReinforcementBarPitchOfWall - Description: isolatie, resolschuim; Reference: 21_RBM_WA_170mm_geïsoleerde_kantplank
Type - Pset_WallCommon - IsExternal: no; Reference: 21_RBM_WA_170mm_geïsoleerde_kantplank
Pset_WallCommon - ExtendToStructure: no; LoadBearing: no; IsExternal: yes
Name (Basic Wall:21_RBM_WA_170mm_geïsoleerde_kantplank:...)
1886116
1886669
1886994
1887892
1887978
1887982
1888419
1972137
2047766
2361678
2640555
2640629
2640833

# IfcWallStandardCase: Basic Wall:21_RBM_WA_dakrand/pas strook_rockpanel (9)
Type - PredefinedType: STANDARD; Material: gevel antraciet 8 mm, ISR_Luchtspouw 35 mm, ISR_Luchtspouw 35 mm, RBM_n7_isolatie_hsb_270 138 mm
Type - Pset_ElementShading - Roughness: 304.8 mm
Type - Pset_ProductRequirements - Category: Walls
Type - Pset_QuantityTakeOff - Reference: 21_RBM_WA_dakrand/pas strook_rockpanel
Type - Pset_ReinforcementBarPitchOfWall - Description: isolatie, resolschuim; Reference: 21_RBM_WA_dakrand/pas strook_rockpanel
Type - Pset_WallCommon - IsExternal: no; Reference: 21_RBM_WA_dakrand/pas strook_rockpanel
Pset_WallCommon - ExtendToStructure: no; LoadBearing: no; IsExternal: yes
Name (Basic Wall:21_RBM_WA_dakrand/pas strook_rockpanel:...) | In
1886504 | 02 tweede verdieping
1889003 | 01 eerste verdieping
2654662 | 02 tweede verdieping
2681180 | 03 dak
2682410 | 03 dak
2684279 | 03 dak
2731676 | 03 dak
2731722 | 03 dak
2741240 | 02 tweede verdieping

# IfcWallStandardCase: Basic Wall:21_RBM_WA_dakrand_beplating_rockpanel (4)
In: 00 begane grond
Type - PredefinedType: STANDARD; Material: gevel antraciet 8 mm, RBM_i2_hout_vuren_gen 35 mm, RBM_i2_hout_vuren_gen 35 mm
Type - Pset_ElementShading - Roughness: 304.8 mm
Type - Pset_ProductRequirements - Category: Walls
Type - Pset_QuantityTakeOff - Reference: 21_RBM_WA_dakrand_beplating_rockpanel
Type - Pset_ReinforcementBarPitchOfWall - Description: isolatie, resolschuim; Reference: 21_RBM_WA_dakrand_beplating_rockpanel
Type - Pset_WallCommon - IsExternal: no; Reference: 21_RBM_WA_dakrand_beplating_rockpanel; ThermalTransmittance: 1.71429 kg/K/s3
Pset_WallCommon - ExtendToStructure: no; LoadBearing: no; IsExternal: yes
Name (Basic Wall:21_RBM_WA_dakrand_beplating_rockpanel:...)
2749810
2750308
2750965
2751185

# IfcWallStandardCase: Basic Wall:21_RBM_WA_hsb_270mm + rockpanel +afwerking gips binnen, Basic Wall:21_RBM_WA_hsb_270mm + rockpanel +afwerking gips binnen:2732826
In: 02 tweede verdieping
Type - PredefinedType: STANDARD; Material: gevel antraciet 8 mm, ISR_Luchtspouw 35 mm, ISR_Luchtspouw 35 mm, RBM_n7_isolatie_hsb_270 270 mm, RBM_i4_multiplex_beplating 18 mm, RBM_f7_gips_beplating wand 12.5 mm
Type - Pset_ElementShading - Roughness: 304.8 mm
Type - Pset_ProductRequirements - Category: Walls
Type - Pset_QuantityTakeOff - Reference: 21_RBM_WA_hsb_270mm + rockpanel +afwerking gips binnen
Type - Pset_ReinforcementBarPitchOfWall - Description: hsb element 196mm, buitenafwerking: osb plaat met wind- en waterkerende folie, binnenwafwerking: osb plaat in het zicht; Reference: 21_RBM_WA_hsb_270mm + rockpanel +afwerking gips binnen
Type - Pset_WallCommon - IsExternal: no; Reference: 21_RBM_WA_hsb_270mm + rockpanel +afwerking gips binnen; ThermalTransmittance: 5.88889 kg/K/s3
Pset_WallCommon - ExtendToStructure: no; LoadBearing: no; IsExternal: yes

# IfcWallStandardCase: Basic Wall:21_RBM_WA_hsb_270mm - geïsoleerd (3)
In: 00 begane grond
Type - PredefinedType: STANDARD; Material: RBM_n7_isolatie_hsb_270 270 mm, RBM_i4_multiplex_beplating 18 mm
Type - Pset_ElementShading - Roughness: 304.8 mm
Type - Pset_ProductRequirements - Category: Walls
Type - Pset_QuantityTakeOff - Reference: 21_RBM_WA_hsb_270mm - geïsoleerd
Type - Pset_ReinforcementBarPitchOfWall - Description: hsb element 196mm, buitenafwerking: osb plaat met wind- en waterkerende folie, binnenwafwerking: osb plaat in het zicht; Reference: 21_RBM_WA_hsb_270mm - geïsoleerd
Type - Pset_WallCommon - IsExternal: no; Reference: 21_RBM_WA_hsb_270mm - geïsoleerd; ThermalTransmittance: 5.88889 kg/K/s3
Pset_WallCommon - ExtendToStructure: no; LoadBearing: no; IsExternal: yes
Name (Basic Wall:21_RBM_WA_hsb_270mm - geïsoleerd:...)
1643321
1778975
2744418

# IfcWallStandardCase: Basic Wall:21_RBM_WA_hsb_270mm - niet geïsoleerd (3)
In: 00 begane grond
Type - PredefinedType: STANDARD; Material: ISR_Luchtspouw 270 mm, RBM_i4_multiplex_beplating 18 mm
Type - Pset_ElementShading - Roughness: 304.8 mm
Type - Pset_ProductRequirements - Category: Walls
Type - Pset_QuantityTakeOff - Reference: 21_RBM_WA_hsb_270mm - niet geïsoleerd
Type - Pset_ReinforcementBarPitchOfWall - Description: hsb element 196mm, buitenafwerking: osb plaat met wind- en waterkerende folie, binnenwafwerking: osb plaat in het zicht; Reference: 21_RBM_WA_hsb_270mm - niet geïsoleerd
Type - Pset_WallCommon - IsExternal: no; Reference: 21_RBM_WA_hsb_270mm - niet geïsoleerd; ThermalTransmittance: 5.88889 kg/K/s3
Pset_WallCommon - ExtendToStructure: no; LoadBearing: no; IsExternal: yes
Name (Basic Wall:21_RBM_WA_hsb_270mm - niet geïsoleerd:...)
1977456
1977517
2740495

# IfcWallStandardCase: Basic Wall:21_RBM_WA_hsb_270mm_ rockpanel (8)
Type - PredefinedType: STANDARD; Material: gevel antraciet 8 mm, ISR_Luchtspouw 35 mm, ISR_Luchtspouw 35 mm, RBM_n7_isolatie_hsb_270 270 mm, RBM_i4_multiplex_beplating 18 mm
Type - Pset_ElementShading - Roughness: 304.8 mm
Type - Pset_ProductRequirements - Category: Walls
Type - Pset_QuantityTakeOff - Reference: 21_RBM_WA_hsb_270mm_ rockpanel
Type - Pset_ReinforcementBarPitchOfWall - Description: hsb element 196mm, buitenafwerking: osb plaat met wind- en waterkerende folie, binnenwafwerking: osb plaat in het zicht; Reference: 21_RBM_WA_hsb_270mm_ rockpanel
Type - Pset_WallCommon - IsExternal: no; Reference: 21_RBM_WA_hsb_270mm_ rockpanel; ThermalTransmittance: 5.88889 kg/K/s3
Pset_WallCommon - ExtendToStructure: no; LoadBearing: no; IsExternal: yes
Name (Basic Wall:21_RBM_WA_hsb_270mm_ rockpanel:...) | In
1886505 | 02 tweede verdieping
1887979 | 00 begane grond
1887983 | 00 begane grond
1888420 | 00 begane grond
1888480 | 02 tweede verdieping
1972138 | 00 begane grond
2454753 | 02 tweede verdieping
2754429 | 01 eerste verdieping

# IfcWallStandardCase: Basic Wall:21_RBM_WA_hsb_270mm_houten bekleding (6)
Type - PredefinedType: STANDARD; Material: Gevelafwerking 30 mm, ISR_Luchtspouw 35 mm, ISR_Luchtspouw 35 mm, RBM_n7_isolatie_hsb_270 270 mm, RBM_i4_multiplex_beplating 18 mm
Type - Pset_ElementShading - Roughness: 304.8 mm
Type - Pset_ProductRequirements - Category: Walls
Type - Pset_QuantityTakeOff - Reference: 21_RBM_WA_hsb_270mm_houten bekleding
Type - Pset_ReinforcementBarPitchOfWall - Description: hsb element 196mm, buitenafwerking: osb plaat met wind- en waterkerende folie, binnenwafwerking: osb plaat in het zicht; Reference: 21_RBM_WA_hsb_270mm_houten bekleding
Type - Pset_WallCommon - IsExternal: no; Reference: 21_RBM_WA_hsb_270mm_houten bekleding; ThermalTransmittance: 5.88889 kg/K/s3
Pset_WallCommon - LoadBearing: no; IsExternal: yes
Name (Basic Wall:21_RBM_WA_hsb_270mm_houten bekleding:...) | In | ExtendToStructure
1886670 | 00 begane grond | no
1886995 | 00 begane grond | no
1887040 | 01 eerste verdieping | yes
1887893 | 00 begane grond | no
2520221 | 00 begane grond | no
2747179 | 00 begane grond | no

# IfcWallStandardCase: Basic Wall:21_RBM_WA_passtrook_BU_houten bekleding, Basic Wall:21_RBM_WA_passtrook_BU_houten bekleding:1887039
In: 01 eerste verdieping
Type - PredefinedType: STANDARD; Material: Gevelafwerking 30 mm, ISR_Luchtspouw 35 mm, ISR_Luchtspouw 35 mm, RBM_n7_isolatie_hsb_invulling 138 mm
Type - Pset_ElementShading - Roughness: 304.8 mm
Type - Pset_ProductRequirements - Category: Walls
Type - Pset_QuantityTakeOff - Reference: 21_RBM_WA_passtrook_BU_houten bekleding
Type - Pset_ReinforcementBarPitchOfWall - Description: isolatie, resolschuim; Reference: 21_RBM_WA_passtrook_BU_houten bekleding
Type - Pset_WallCommon - IsExternal: no; Reference: 21_RBM_WA_passtrook_BU_houten bekleding
Pset_WallCommon - ExtendToStructure: no; LoadBearing: no; IsExternal: yes

# IfcWallStandardCase: Basic Wall:21_hsb_100mm, Basic Wall:21_hsb_100mm:1782067
In: 00 begane grond
Type - PredefinedType: STANDARD; Material: gevel antraciet 20 mm, RBM_n7_isolatie_hsb_100 100 mm
Type - Pset_ElementShading - Roughness: 304.8 mm
Type - Pset_ProductRequirements - Category: Walls
Type - Pset_QuantityTakeOff - Reference: 21_hsb_100mm
Type - Pset_ReinforcementBarPitchOfWall - Reference: 21_hsb_100mm
Type - Pset_WallCommon - IsExternal: no; Reference: 21_hsb_100mm
Pset_QuantityTakeOff - sets with these values: 2
Pset_WallCommon - ExtendToStructure: no; LoadBearing: no

# IfcWallStandardCase: Basic Wall:22_RBM_WA_metalstud_70_12.5-45-12.5 (2)
Type - PredefinedType: STANDARD; Material: RBM_f7_gips_beplating wand 12.5 mm, RBM_n7_isolatie_MS45 45 mm, RBM_f7_gips_beplating wand 12.5 mm
Type - Pset_ElementShading - Roughness: 304.8 mm
Type - Pset_ProductRequirements - Category: Walls
Type - Pset_QuantityTakeOff - Reference: 22_RBM_WA_metalstud_70_12.5-45-12.5
Type - Pset_ReinforcementBarPitchOfWall - Description: metalstudwand; Reference: 22_RBM_WA_metalstud_70_12.5-45-12.5
Type - Pset_WallCommon - IsExternal: no; Reference: 22_RBM_WA_metalstud_70_12.5-45-12.5
Pset_WallCommon - LoadBearing: no; IsExternal: yes
Name (Basic Wall:22_RBM_WA_metalstud_70_12.5-45-12.5:...) | In | ExtendToStructure
1749284 | 01 eerste verdieping | yes
1786324 | 00 begane grond | no

# IfcWallStandardCase: Basic Wall:22_RBM_WA_ontwerpwand-40mm (4)
In: 00 begane grond
Type - PredefinedType: STANDARD; Material: <Unnamed> 50 mm
Type - Pset_ElementShading - Roughness: 304.8 mm
Type - Pset_ProductRequirements - Category: Walls
Type - Pset_QuantityTakeOff - Reference: 22_RBM_WA_ontwerpwand-40mm
Type - Pset_ReinforcementBarPitchOfWall - Description: buitenwand, generiek; Reference: 22_RBM_WA_ontwerpwand-40mm
Type - Pset_WallCommon - IsExternal: no; Reference: 22_RBM_WA_ontwerpwand-40mm
Pset_WallCommon - LoadBearing: no; IsExternal: yes
Group: Model Group:Lift:2178208
Name (Basic Wall:22_RBM_WA_ontwerpwand-40mm:...) | ExtendToStructure
1770855 | yes
1770856 | yes
2177971 | no
2178088 | yes

# IfcWallStandardCase: Basic Wall:22_RBM_WA_ontwerpwand-40mm_transparant (3)
In: 00 begane grond
Type - PredefinedType: STANDARD; Material: RBM_o1_glas_helder 50 mm
Type - Pset_ElementShading - Roughness: 304.8 mm
Type - Pset_ProductRequirements - Category: Walls
Type - Pset_QuantityTakeOff - Reference: 22_RBM_WA_ontwerpwand-40mm_transparant
Type - Pset_ReinforcementBarPitchOfWall - Description: buitenwand, generiek; Reference: 22_RBM_WA_ontwerpwand-40mm_transparant
Type - Pset_WallCommon - IsExternal: no; Reference: 22_RBM_WA_ontwerpwand-40mm_transparant; ThermalTransmittance: 22 kg/K/s3
Pset_WallCommon - LoadBearing: no; ExtendToStructure: yes; IsExternal: yes
Group: Model Group:Lift:2178208
Name (Basic Wall:22_RBM_WA_ontwerpwand-40mm_transparant:...)
1770853
1770854
2178169

# IfcWallStandardCase: Basic Wall:22_WA_hsb_binnenwand_306mm (3)
In: 00 begane grond
Type - PredefinedType: STANDARD; Material: RBM_i4_multiplex_beplating 18 mm, RBM_n7_isolatie_hsb_270 270 mm, RBM_i4_multiplex_beplating 18 mm
Type - Pset_ElementShading - Roughness: 304.8 mm
Type - Pset_ProductRequirements - Category: Walls
Type - Pset_QuantityTakeOff - Reference: 22_WA_hsb_binnenwand_306mm
Type - Pset_ReinforcementBarPitchOfWall - Reference: 22_WA_hsb_binnenwand_306mm
Type - Pset_WallCommon - IsExternal: no; Reference: 22_WA_hsb_binnenwand_306mm; ThermalTransmittance: 2.94444 kg/K/s3
Pset_QuantityTakeOff - sets with these values: 2
Pset_WallCommon - ExtendToStructure: no; LoadBearing: no
Name (Basic Wall:22_WA_hsb_binnenwand_306mm:...)
1642337
1888207
2505107

# IfcWallStandardCase: Basic Wall:22_WA_metalstud_binnenwand_100mm (14)
Type - PredefinedType: STANDARD; Material: RBM_n7_isolatie_hsb_100 100 mm
Type - Pset_ElementShading - Roughness: 304.8 mm
Type - Pset_ProductRequirements - Category: Walls
Type - Pset_QuantityTakeOff - Reference: 22_WA_metalstud_binnenwand_100mm
Type - Pset_ReinforcementBarPitchOfWall - Reference: 22_WA_metalstud_binnenwand_100mm
Type - Pset_WallCommon - IsExternal: no; Reference: 22_WA_metalstud_binnenwand_100mm
Pset_QuantityTakeOff - sets with these values: 2
Pset_WallCommon - LoadBearing: no
Name (Basic Wall:22_WA_metalstud_binnenwand_100mm:...) | In | ExtendToStructure
1641766 | 00 begane grond | yes
1641830 | 00 begane grond | no
1641944 | 00 begane grond | no
1642114 | 00 begane grond | yes
1657728 | 00 begane grond | no
1657769 | 00 begane grond | yes
1657880 | 01 eerste verdieping | yes
1657975 | 01 eerste verdieping | yes
1658055 | 01 eerste verdieping | yes
1658157 | 01 eerste verdieping | yes
1658265 | 01 eerste verdieping | yes
1748973 | 01 eerste verdieping | yes
1749211 | 01 eerste verdieping | yes
2391560 | 01 eerste verdieping | yes

# IfcWallStandardCase: Basic Wall:22_hsb_270 passtrook (3)
In: 00 begane grond
Type - PredefinedType: STANDARD; Material: RBM_n7_isolatie_hsb_270 132 mm, RBM_i4_multiplex_beplating 18 mm
Type - Pset_ElementShading - Roughness: 304.8 mm
Type - Pset_ProductRequirements - Category: Walls
Type - Pset_QuantityTakeOff - Reference: 22_hsb_270 passtrook
Type - Pset_ReinforcementBarPitchOfWall - Reference: 22_hsb_270 passtrook
Type - Pset_WallCommon - IsExternal: no; Reference: 22_hsb_270 passtrook; ThermalTransmittance: 5.88889 kg/K/s3
Pset_QuantityTakeOff - sets with these values: 2
Pset_WallCommon - LoadBearing: no
Name (Basic Wall:22_hsb_270 passtrook:...) | ExtendToStructure
2736768 | yes
2748201 | no
2748499 | no

# IfcWallStandardCase: Basic Wall:22_hsb_270 passtrook + 6, Basic Wall:22_hsb_270 passtrook + 6:2812115
In: 02 tweede verdieping
Type - PredefinedType: STANDARD; Material: RBM_n7_isolatie_hsb_270 138 mm, RBM_i4_multiplex_beplating 18 mm
Type - Pset_ElementShading - Roughness: 304.8 mm
Type - Pset_ProductRequirements - Category: Walls
Type - Pset_QuantityTakeOff - Reference: 22_hsb_270 passtrook + 6
Type - Pset_ReinforcementBarPitchOfWall - Reference: 22_hsb_270 passtrook + 6
Type - Pset_WallCommon - IsExternal: no; Reference: 22_hsb_270 passtrook + 6; ThermalTransmittance: 5.88889 kg/K/s3
Pset_QuantityTakeOff - sets with these values: 2
Pset_WallCommon - ExtendToStructure: no; LoadBearing: no

# IfcWallStandardCase: Basic Wall:22_hsb_270 passtrook + gips (3)
Type - PredefinedType: STANDARD; Material: RBM_n7_isolatie_hsb_270 132 mm, RBM_i4_multiplex_beplating 18 mm, RBM_f7_gips_beplating wand 12.5 mm
Type - Pset_ElementShading - Roughness: 304.8 mm
Type - Pset_ProductRequirements - Category: Walls
Type - Pset_QuantityTakeOff - Reference: 22_hsb_270 passtrook + gips
Type - Pset_ReinforcementBarPitchOfWall - Reference: 22_hsb_270 passtrook + gips
Type - Pset_WallCommon - IsExternal: no; Reference: 22_hsb_270 passtrook + gips; ThermalTransmittance: 5.88889 kg/K/s3
Pset_QuantityTakeOff - sets with these values: 2
Pset_WallCommon - ExtendToStructure: no; LoadBearing: no
Name (Basic Wall:22_hsb_270 passtrook + gips:...) | In
2752296 | 02 tweede verdieping
2752812 | 02 tweede verdieping
2753440 | 01 eerste verdieping

# IfcWallStandardCase: Basic Wall:22_hsb_binnenwand_gips_318,5mm (6)
Type - PredefinedType: STANDARD; Material: RBM_f7_gips_beplating wand 12.5 mm, RBM_i4_multiplex_beplating 18 mm, RBM_n7_isolatie_hsb_270 270 mm, RBM_i4_multiplex_beplating 18 mm
Type - Pset_ElementShading - Roughness: 304.8 mm
Type - Pset_ProductRequirements - Category: Walls
Type - Pset_QuantityTakeOff - Reference: 22_hsb_binnenwand_gips_318,5mm
Type - Pset_ReinforcementBarPitchOfWall - Reference: 22_hsb_binnenwand_gips_318,5mm
Type - Pset_WallCommon - Reference: 22_hsb_binnenwand_gips_318,5mm; ThermalTransmittance: 2.94444 kg/K/s3; IsExternal: no
Pset_QuantityTakeOff - sets with these values: 2
Pset_WallCommon - LoadBearing: no
Name (Basic Wall:22_hsb_binnenwand_gips_318,5mm:...) | In | ExtendToStructure
1641471 | 00 begane grond | no
1641685 | 00 begane grond | no
1653860 | 02 tweede verdieping | yes
1653861 | 01 eerste verdieping | yes
1660133 | 01 eerste verdieping | yes
1970625 | 00 begane grond | no

# IfcWindow: WI_subvak:glas 2 (23)
Type - ParameterTakesPrecedence: no; Sizeable: no; Material: o1_glas
Type - Pset_ManufacturerTypeInformation - Manufacturer: ITANNEX
Type - Pset_ProductRequirements - Category: Windows
Type - Pset_QuantityTakeOff - Reference: glas 2
Type - Pset_WindowCommon - IsExternal: no; Reference: glas 2
Name (WI_subvak:glas 2:...) | In | OverallHeight (mm) | OverallWidth (mm) | Group
1694406 | 00 begane grond | 2206.5 | 882.348 | Model Group:vliesgevel A:2175042
1694407 | 00 begane grond | 2206.5 | 882.348 | Model Group:vliesgevel A:2175042
1712432 | 00 begane grond | 1058.5 | 596.5
1712476 | 00 begane grond | 1058.5 | 610
1712478 | 00 begane grond | 890 | 610
1771785 | 00 begane grond | 2173 | 526.5 | Model Group:H05:2174889
1771786 | 00 begane grond | 2173 | 526.5 | Model Group:H05:2174889
1773415 | 02 tweede verdieping | 2173 | 476.5 | Model Group:32_dubbele deur:2147310
1773416 | 02 tweede verdieping | 2173 | 476.5 | Model Group:32_dubbele deur:2147310
1774062 | 00 begane grond | 2173 | 526.5
1774063 | 00 begane grond | 2173 | 526.5
2317231 | 00 begane grond | 2206.5 | 821.227 | Model Group:vliesgevel C:2317233
2317232 | 00 begane grond | 2206.5 | 821.227 | Model Group:vliesgevel C:2317233
2536678 | 00 begane grond | 2051.17 | 969.01 | Model Group:Vliesgevel B:2773624
2536679 | 00 begane grond | 2051.17 | 969.01 | Model Group:Vliesgevel B:2773624
2756333 | 00 begane grond | 2206.5 | 882.348
2756334 | 00 begane grond | 2206.5 | 882.348
2757096 | 00 begane grond | 2173 | 526.5 | Model Group:H05:2757098
2757097 | 00 begane grond | 2173 | 526.5 | Model Group:H05:2757098
2757197 | 00 begane grond | 2206.5 | 821.227
2757198 | 00 begane grond | 2206.5 | 821.227
2757487 | 00 begane grond | 2206.5 | 969.01
2757488 | 00 begane grond | 2206.5 | 969.01
